VERSION 5.8 ;
BUSBITCHARS "[]" ;
DIVIDERCHAR "/" ;
UNITS
    DATABASE MICRONS 1000 ;
END UNITS

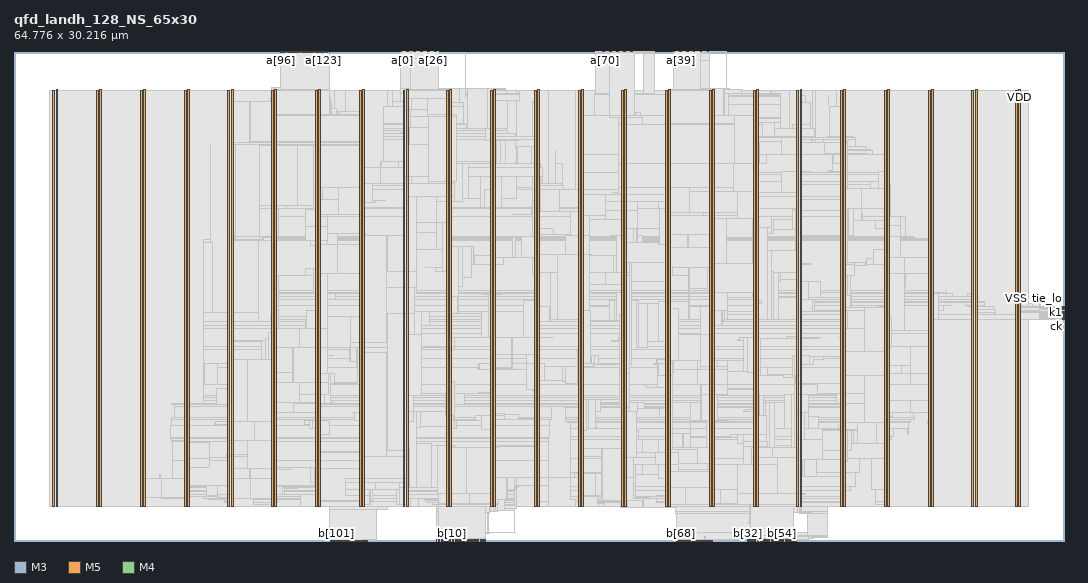
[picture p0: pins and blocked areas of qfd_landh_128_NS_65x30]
MACRO qfd_landh_128_NS_65x30
  FOREIGN qfd_landh_128_NS_65x30 0 0 ;
  CLASS BLOCK ;
  SIZE 64.776 BY 30.216 ;
  PIN a[0]
    DIRECTION INPUT ;
    USE SIGNAL ;
    PORT
      LAYER M3 ;
        RECT  23.94 30.179 23.958 30.216 ;
    END
  END a[0]
  PIN a[100]
    DIRECTION INPUT ;
    USE SIGNAL ;
    PORT
      LAYER M5 ;
        RECT  16.848 30.132 16.872 30.216 ;
    END
  END a[100]
  PIN a[101]
    DIRECTION INPUT ;
    USE SIGNAL ;
    PORT
      LAYER M5 ;
        RECT  16.944 30.132 16.968 30.216 ;
    END
  END a[101]
  PIN a[102]
    DIRECTION INPUT ;
    USE SIGNAL ;
    PORT
      LAYER M5 ;
        RECT  17.04 30.132 17.064 30.216 ;
    END
  END a[102]
  PIN a[103]
    DIRECTION INPUT ;
    USE SIGNAL ;
    PORT
      LAYER M5 ;
        RECT  17.136 30.132 17.16 30.216 ;
    END
  END a[103]
  PIN a[104]
    DIRECTION INPUT ;
    USE SIGNAL ;
    PORT
      LAYER M5 ;
        RECT  17.232 30.132 17.256 30.216 ;
    END
  END a[104]
  PIN a[105]
    DIRECTION INPUT ;
    USE SIGNAL ;
    PORT
      LAYER M5 ;
        RECT  17.328 30.132 17.352 30.216 ;
    END
  END a[105]
  PIN a[106]
    DIRECTION INPUT ;
    USE SIGNAL ;
    PORT
      LAYER M5 ;
        RECT  17.424 30.132 17.448 30.216 ;
    END
  END a[106]
  PIN a[107]
    DIRECTION INPUT ;
    USE SIGNAL ;
    PORT
      LAYER M5 ;
        RECT  17.52 30.132 17.544 30.216 ;
    END
  END a[107]
  PIN a[108]
    DIRECTION INPUT ;
    USE SIGNAL ;
    PORT
      LAYER M5 ;
        RECT  17.616 30.132 17.64 30.216 ;
    END
  END a[108]
  PIN a[109]
    DIRECTION INPUT ;
    USE SIGNAL ;
    PORT
      LAYER M5 ;
        RECT  17.712 30.132 17.736 30.216 ;
    END
  END a[109]
  PIN a[10]
    DIRECTION INPUT ;
    USE SIGNAL ;
    PORT
      LAYER M3 ;
        RECT  24.66 30.179 24.678 30.216 ;
    END
  END a[10]
  PIN a[110]
    DIRECTION INPUT ;
    USE SIGNAL ;
    PORT
      LAYER M5 ;
        RECT  17.808 30.132 17.832 30.216 ;
    END
  END a[110]
  PIN a[111]
    DIRECTION INPUT ;
    USE SIGNAL ;
    PORT
      LAYER M5 ;
        RECT  17.904 30.132 17.928 30.216 ;
    END
  END a[111]
  PIN a[112]
    DIRECTION INPUT ;
    USE SIGNAL ;
    PORT
      LAYER M5 ;
        RECT  18 30.132 18.024 30.216 ;
    END
  END a[112]
  PIN a[113]
    DIRECTION INPUT ;
    USE SIGNAL ;
    PORT
      LAYER M5 ;
        RECT  18.096 30.132 18.12 30.216 ;
    END
  END a[113]
  PIN a[114]
    DIRECTION INPUT ;
    USE SIGNAL ;
    PORT
      LAYER M5 ;
        RECT  18.192 30.132 18.216 30.216 ;
    END
  END a[114]
  PIN a[115]
    DIRECTION INPUT ;
    USE SIGNAL ;
    PORT
      LAYER M5 ;
        RECT  18.288 30.132 18.312 30.216 ;
    END
  END a[115]
  PIN a[116]
    DIRECTION INPUT ;
    USE SIGNAL ;
    PORT
      LAYER M5 ;
        RECT  18.384 30.132 18.408 30.216 ;
    END
  END a[116]
  PIN a[117]
    DIRECTION INPUT ;
    USE SIGNAL ;
    PORT
      LAYER M5 ;
        RECT  18.48 30.132 18.504 30.216 ;
    END
  END a[117]
  PIN a[118]
    DIRECTION INPUT ;
    USE SIGNAL ;
    PORT
      LAYER M5 ;
        RECT  18.576 30.132 18.6 30.216 ;
    END
  END a[118]
  PIN a[119]
    DIRECTION INPUT ;
    USE SIGNAL ;
    PORT
      LAYER M5 ;
        RECT  18.672 30.132 18.696 30.216 ;
    END
  END a[119]
  PIN a[11]
    DIRECTION INPUT ;
    USE SIGNAL ;
    PORT
      LAYER M3 ;
        RECT  24.732 30.179 24.75 30.216 ;
    END
  END a[11]
  PIN a[120]
    DIRECTION INPUT ;
    USE SIGNAL ;
    PORT
      LAYER M5 ;
        RECT  18.768 30.132 18.792 30.216 ;
    END
  END a[120]
  PIN a[121]
    DIRECTION INPUT ;
    USE SIGNAL ;
    PORT
      LAYER M5 ;
        RECT  18.864 30.132 18.888 30.216 ;
    END
  END a[121]
  PIN a[122]
    DIRECTION INPUT ;
    USE SIGNAL ;
    PORT
      LAYER M5 ;
        RECT  18.96 30.132 18.984 30.216 ;
    END
  END a[122]
  PIN a[123]
    DIRECTION INPUT ;
    USE SIGNAL ;
    PORT
      LAYER M5 ;
        RECT  19.056 30.132 19.08 30.216 ;
    END
  END a[123]
  PIN a[124]
    DIRECTION INPUT ;
    USE SIGNAL ;
    PORT
      LAYER M5 ;
        RECT  19.152 30.132 19.176 30.216 ;
    END
  END a[124]
  PIN a[125]
    DIRECTION INPUT ;
    USE SIGNAL ;
    PORT
      LAYER M5 ;
        RECT  19.248 30.132 19.272 30.216 ;
    END
  END a[125]
  PIN a[126]
    DIRECTION INPUT ;
    USE SIGNAL ;
    PORT
      LAYER M5 ;
        RECT  19.344 30.132 19.368 30.216 ;
    END
  END a[126]
  PIN a[127]
    DIRECTION INPUT ;
    USE SIGNAL ;
    PORT
      LAYER M5 ;
        RECT  19.44 30.132 19.464 30.216 ;
    END
  END a[127]
  PIN a[12]
    DIRECTION INPUT ;
    USE SIGNAL ;
    PORT
      LAYER M3 ;
        RECT  24.804 30.179 24.822 30.216 ;
    END
  END a[12]
  PIN a[13]
    DIRECTION INPUT ;
    USE SIGNAL ;
    PORT
      LAYER M3 ;
        RECT  24.876 30.179 24.894 30.216 ;
    END
  END a[13]
  PIN a[14]
    DIRECTION INPUT ;
    USE SIGNAL ;
    PORT
      LAYER M3 ;
        RECT  24.948 30.179 24.966 30.216 ;
    END
  END a[14]
  PIN a[15]
    DIRECTION INPUT ;
    USE SIGNAL ;
    PORT
      LAYER M3 ;
        RECT  25.02 30.179 25.038 30.216 ;
    END
  END a[15]
  PIN a[16]
    DIRECTION INPUT ;
    USE SIGNAL ;
    PORT
      LAYER M3 ;
        RECT  25.092 30.179 25.11 30.216 ;
    END
  END a[16]
  PIN a[17]
    DIRECTION INPUT ;
    USE SIGNAL ;
    PORT
      LAYER M3 ;
        RECT  25.164 30.179 25.182 30.216 ;
    END
  END a[17]
  PIN a[18]
    DIRECTION INPUT ;
    USE SIGNAL ;
    PORT
      LAYER M3 ;
        RECT  25.236 30.179 25.254 30.216 ;
    END
  END a[18]
  PIN a[19]
    DIRECTION INPUT ;
    USE SIGNAL ;
    PORT
      LAYER M3 ;
        RECT  25.308 30.179 25.326 30.216 ;
    END
  END a[19]
  PIN a[1]
    DIRECTION INPUT ;
    USE SIGNAL ;
    PORT
      LAYER M3 ;
        RECT  24.012 30.179 24.03 30.216 ;
    END
  END a[1]
  PIN a[20]
    DIRECTION INPUT ;
    USE SIGNAL ;
    PORT
      LAYER M3 ;
        RECT  25.38 30.179 25.398 30.216 ;
    END
  END a[20]
  PIN a[21]
    DIRECTION INPUT ;
    USE SIGNAL ;
    PORT
      LAYER M3 ;
        RECT  25.452 30.179 25.47 30.216 ;
    END
  END a[21]
  PIN a[22]
    DIRECTION INPUT ;
    USE SIGNAL ;
    PORT
      LAYER M3 ;
        RECT  25.524 30.179 25.542 30.216 ;
    END
  END a[22]
  PIN a[23]
    DIRECTION INPUT ;
    USE SIGNAL ;
    PORT
      LAYER M3 ;
        RECT  25.596 30.179 25.614 30.216 ;
    END
  END a[23]
  PIN a[24]
    DIRECTION INPUT ;
    USE SIGNAL ;
    PORT
      LAYER M3 ;
        RECT  25.668 30.179 25.686 30.216 ;
    END
  END a[24]
  PIN a[25]
    DIRECTION INPUT ;
    USE SIGNAL ;
    PORT
      LAYER M3 ;
        RECT  25.74 30.179 25.758 30.216 ;
    END
  END a[25]
  PIN a[26]
    DIRECTION INPUT ;
    USE SIGNAL ;
    PORT
      LAYER M3 ;
        RECT  25.812 30.179 25.83 30.216 ;
    END
  END a[26]
  PIN a[27]
    DIRECTION INPUT ;
    USE SIGNAL ;
    PORT
      LAYER M3 ;
        RECT  25.884 30.179 25.902 30.216 ;
    END
  END a[27]
  PIN a[28]
    DIRECTION INPUT ;
    USE SIGNAL ;
    PORT
      LAYER M3 ;
        RECT  25.956 30.179 25.974 30.216 ;
    END
  END a[28]
  PIN a[29]
    DIRECTION INPUT ;
    USE SIGNAL ;
    PORT
      LAYER M3 ;
        RECT  26.028 30.179 26.046 30.216 ;
    END
  END a[29]
  PIN a[2]
    DIRECTION INPUT ;
    USE SIGNAL ;
    PORT
      LAYER M3 ;
        RECT  24.084 30.179 24.102 30.216 ;
    END
  END a[2]
  PIN a[30]
    DIRECTION INPUT ;
    USE SIGNAL ;
    PORT
      LAYER M3 ;
        RECT  26.1 30.179 26.118 30.216 ;
    END
  END a[30]
  PIN a[31]
    DIRECTION INPUT ;
    USE SIGNAL ;
    PORT
      LAYER M3 ;
        RECT  26.172 30.179 26.19 30.216 ;
    END
  END a[31]
  PIN a[32]
    DIRECTION INPUT ;
    USE SIGNAL ;
    PORT
      LAYER M3 ;
        RECT  40.644 30.179 40.662 30.216 ;
    END
  END a[32]
  PIN a[33]
    DIRECTION INPUT ;
    USE SIGNAL ;
    PORT
      LAYER M3 ;
        RECT  40.716 30.179 40.734 30.216 ;
    END
  END a[33]
  PIN a[34]
    DIRECTION INPUT ;
    USE SIGNAL ;
    PORT
      LAYER M3 ;
        RECT  40.788 30.179 40.806 30.216 ;
    END
  END a[34]
  PIN a[35]
    DIRECTION INPUT ;
    USE SIGNAL ;
    PORT
      LAYER M3 ;
        RECT  40.86 30.179 40.878 30.216 ;
    END
  END a[35]
  PIN a[36]
    DIRECTION INPUT ;
    USE SIGNAL ;
    PORT
      LAYER M3 ;
        RECT  40.932 30.179 40.95 30.216 ;
    END
  END a[36]
  PIN a[37]
    DIRECTION INPUT ;
    USE SIGNAL ;
    PORT
      LAYER M3 ;
        RECT  41.004 30.179 41.022 30.216 ;
    END
  END a[37]
  PIN a[38]
    DIRECTION INPUT ;
    USE SIGNAL ;
    PORT
      LAYER M3 ;
        RECT  41.076 30.179 41.094 30.216 ;
    END
  END a[38]
  PIN a[39]
    DIRECTION INPUT ;
    USE SIGNAL ;
    PORT
      LAYER M3 ;
        RECT  41.148 30.179 41.166 30.216 ;
    END
  END a[39]
  PIN a[3]
    DIRECTION INPUT ;
    USE SIGNAL ;
    PORT
      LAYER M3 ;
        RECT  24.156 30.179 24.174 30.216 ;
    END
  END a[3]
  PIN a[40]
    DIRECTION INPUT ;
    USE SIGNAL ;
    PORT
      LAYER M3 ;
        RECT  41.22 30.179 41.238 30.216 ;
    END
  END a[40]
  PIN a[41]
    DIRECTION INPUT ;
    USE SIGNAL ;
    PORT
      LAYER M3 ;
        RECT  41.292 30.179 41.31 30.216 ;
    END
  END a[41]
  PIN a[42]
    DIRECTION INPUT ;
    USE SIGNAL ;
    PORT
      LAYER M3 ;
        RECT  41.364 30.179 41.382 30.216 ;
    END
  END a[42]
  PIN a[43]
    DIRECTION INPUT ;
    USE SIGNAL ;
    PORT
      LAYER M3 ;
        RECT  41.436 30.179 41.454 30.216 ;
    END
  END a[43]
  PIN a[44]
    DIRECTION INPUT ;
    USE SIGNAL ;
    PORT
      LAYER M3 ;
        RECT  41.508 30.179 41.526 30.216 ;
    END
  END a[44]
  PIN a[45]
    DIRECTION INPUT ;
    USE SIGNAL ;
    PORT
      LAYER M3 ;
        RECT  41.58 30.179 41.598 30.216 ;
    END
  END a[45]
  PIN a[46]
    DIRECTION INPUT ;
    USE SIGNAL ;
    PORT
      LAYER M3 ;
        RECT  41.652 30.179 41.67 30.216 ;
    END
  END a[46]
  PIN a[47]
    DIRECTION INPUT ;
    USE SIGNAL ;
    PORT
      LAYER M3 ;
        RECT  41.724 30.179 41.742 30.216 ;
    END
  END a[47]
  PIN a[48]
    DIRECTION INPUT ;
    USE SIGNAL ;
    PORT
      LAYER M3 ;
        RECT  41.796 30.179 41.814 30.216 ;
    END
  END a[48]
  PIN a[49]
    DIRECTION INPUT ;
    USE SIGNAL ;
    PORT
      LAYER M3 ;
        RECT  41.868 30.179 41.886 30.216 ;
    END
  END a[49]
  PIN a[4]
    DIRECTION INPUT ;
    USE SIGNAL ;
    PORT
      LAYER M3 ;
        RECT  24.228 30.179 24.246 30.216 ;
    END
  END a[4]
  PIN a[50]
    DIRECTION INPUT ;
    USE SIGNAL ;
    PORT
      LAYER M3 ;
        RECT  41.94 30.179 41.958 30.216 ;
    END
  END a[50]
  PIN a[51]
    DIRECTION INPUT ;
    USE SIGNAL ;
    PORT
      LAYER M3 ;
        RECT  42.012 30.179 42.03 30.216 ;
    END
  END a[51]
  PIN a[52]
    DIRECTION INPUT ;
    USE SIGNAL ;
    PORT
      LAYER M3 ;
        RECT  42.084 30.179 42.102 30.216 ;
    END
  END a[52]
  PIN a[53]
    DIRECTION INPUT ;
    USE SIGNAL ;
    PORT
      LAYER M3 ;
        RECT  42.156 30.179 42.174 30.216 ;
    END
  END a[53]
  PIN a[54]
    DIRECTION INPUT ;
    USE SIGNAL ;
    PORT
      LAYER M3 ;
        RECT  42.228 30.179 42.246 30.216 ;
    END
  END a[54]
  PIN a[55]
    DIRECTION INPUT ;
    USE SIGNAL ;
    PORT
      LAYER M3 ;
        RECT  42.3 30.179 42.318 30.216 ;
    END
  END a[55]
  PIN a[56]
    DIRECTION INPUT ;
    USE SIGNAL ;
    PORT
      LAYER M3 ;
        RECT  42.372 30.179 42.39 30.216 ;
    END
  END a[56]
  PIN a[57]
    DIRECTION INPUT ;
    USE SIGNAL ;
    PORT
      LAYER M3 ;
        RECT  42.444 30.179 42.462 30.216 ;
    END
  END a[57]
  PIN a[58]
    DIRECTION INPUT ;
    USE SIGNAL ;
    PORT
      LAYER M3 ;
        RECT  42.516 30.179 42.534 30.216 ;
    END
  END a[58]
  PIN a[59]
    DIRECTION INPUT ;
    USE SIGNAL ;
    PORT
      LAYER M3 ;
        RECT  42.588 30.179 42.606 30.216 ;
    END
  END a[59]
  PIN a[5]
    DIRECTION INPUT ;
    USE SIGNAL ;
    PORT
      LAYER M3 ;
        RECT  24.3 30.179 24.318 30.216 ;
    END
  END a[5]
  PIN a[60]
    DIRECTION INPUT ;
    USE SIGNAL ;
    PORT
      LAYER M3 ;
        RECT  42.66 30.179 42.678 30.216 ;
    END
  END a[60]
  PIN a[61]
    DIRECTION INPUT ;
    USE SIGNAL ;
    PORT
      LAYER M3 ;
        RECT  42.732 30.179 42.75 30.216 ;
    END
  END a[61]
  PIN a[62]
    DIRECTION INPUT ;
    USE SIGNAL ;
    PORT
      LAYER M3 ;
        RECT  42.804 30.179 42.822 30.216 ;
    END
  END a[62]
  PIN a[63]
    DIRECTION INPUT ;
    USE SIGNAL ;
    PORT
      LAYER M3 ;
        RECT  42.876 30.179 42.894 30.216 ;
    END
  END a[63]
  PIN a[64]
    DIRECTION INPUT ;
    USE SIGNAL ;
    PORT
      LAYER M3 ;
        RECT  36.036 30.179 36.054 30.216 ;
    END
  END a[64]
  PIN a[65]
    DIRECTION INPUT ;
    USE SIGNAL ;
    PORT
      LAYER M3 ;
        RECT  36.108 30.179 36.126 30.216 ;
    END
  END a[65]
  PIN a[66]
    DIRECTION INPUT ;
    USE SIGNAL ;
    PORT
      LAYER M3 ;
        RECT  36.18 30.179 36.198 30.216 ;
    END
  END a[66]
  PIN a[67]
    DIRECTION INPUT ;
    USE SIGNAL ;
    PORT
      LAYER M3 ;
        RECT  36.252 30.179 36.27 30.216 ;
    END
  END a[67]
  PIN a[68]
    DIRECTION INPUT ;
    USE SIGNAL ;
    PORT
      LAYER M3 ;
        RECT  36.324 30.179 36.342 30.216 ;
    END
  END a[68]
  PIN a[69]
    DIRECTION INPUT ;
    USE SIGNAL ;
    PORT
      LAYER M3 ;
        RECT  36.396 30.179 36.414 30.216 ;
    END
  END a[69]
  PIN a[6]
    DIRECTION INPUT ;
    USE SIGNAL ;
    PORT
      LAYER M3 ;
        RECT  24.372 30.179 24.39 30.216 ;
    END
  END a[6]
  PIN a[70]
    DIRECTION INPUT ;
    USE SIGNAL ;
    PORT
      LAYER M3 ;
        RECT  36.468 30.179 36.486 30.216 ;
    END
  END a[70]
  PIN a[71]
    DIRECTION INPUT ;
    USE SIGNAL ;
    PORT
      LAYER M3 ;
        RECT  36.54 30.179 36.558 30.216 ;
    END
  END a[71]
  PIN a[72]
    DIRECTION INPUT ;
    USE SIGNAL ;
    PORT
      LAYER M3 ;
        RECT  36.612 30.179 36.63 30.216 ;
    END
  END a[72]
  PIN a[73]
    DIRECTION INPUT ;
    USE SIGNAL ;
    PORT
      LAYER M3 ;
        RECT  36.684 30.179 36.702 30.216 ;
    END
  END a[73]
  PIN a[74]
    DIRECTION INPUT ;
    USE SIGNAL ;
    PORT
      LAYER M3 ;
        RECT  36.756 30.179 36.774 30.216 ;
    END
  END a[74]
  PIN a[75]
    DIRECTION INPUT ;
    USE SIGNAL ;
    PORT
      LAYER M3 ;
        RECT  36.828 30.179 36.846 30.216 ;
    END
  END a[75]
  PIN a[76]
    DIRECTION INPUT ;
    USE SIGNAL ;
    PORT
      LAYER M3 ;
        RECT  36.9 30.179 36.918 30.216 ;
    END
  END a[76]
  PIN a[77]
    DIRECTION INPUT ;
    USE SIGNAL ;
    PORT
      LAYER M3 ;
        RECT  36.972 30.179 36.99 30.216 ;
    END
  END a[77]
  PIN a[78]
    DIRECTION INPUT ;
    USE SIGNAL ;
    PORT
      LAYER M3 ;
        RECT  37.044 30.179 37.062 30.216 ;
    END
  END a[78]
  PIN a[79]
    DIRECTION INPUT ;
    USE SIGNAL ;
    PORT
      LAYER M3 ;
        RECT  37.116 30.179 37.134 30.216 ;
    END
  END a[79]
  PIN a[7]
    DIRECTION INPUT ;
    USE SIGNAL ;
    PORT
      LAYER M3 ;
        RECT  24.444 30.179 24.462 30.216 ;
    END
  END a[7]
  PIN a[80]
    DIRECTION INPUT ;
    USE SIGNAL ;
    PORT
      LAYER M3 ;
        RECT  37.188 30.179 37.206 30.216 ;
    END
  END a[80]
  PIN a[81]
    DIRECTION INPUT ;
    USE SIGNAL ;
    PORT
      LAYER M3 ;
        RECT  37.26 30.179 37.278 30.216 ;
    END
  END a[81]
  PIN a[82]
    DIRECTION INPUT ;
    USE SIGNAL ;
    PORT
      LAYER M3 ;
        RECT  37.332 30.179 37.35 30.216 ;
    END
  END a[82]
  PIN a[83]
    DIRECTION INPUT ;
    USE SIGNAL ;
    PORT
      LAYER M3 ;
        RECT  37.404 30.179 37.422 30.216 ;
    END
  END a[83]
  PIN a[84]
    DIRECTION INPUT ;
    USE SIGNAL ;
    PORT
      LAYER M3 ;
        RECT  37.476 30.179 37.494 30.216 ;
    END
  END a[84]
  PIN a[85]
    DIRECTION INPUT ;
    USE SIGNAL ;
    PORT
      LAYER M3 ;
        RECT  37.548 30.179 37.566 30.216 ;
    END
  END a[85]
  PIN a[86]
    DIRECTION INPUT ;
    USE SIGNAL ;
    PORT
      LAYER M3 ;
        RECT  37.62 30.179 37.638 30.216 ;
    END
  END a[86]
  PIN a[87]
    DIRECTION INPUT ;
    USE SIGNAL ;
    PORT
      LAYER M3 ;
        RECT  37.692 30.179 37.71 30.216 ;
    END
  END a[87]
  PIN a[88]
    DIRECTION INPUT ;
    USE SIGNAL ;
    PORT
      LAYER M3 ;
        RECT  37.764 30.179 37.782 30.216 ;
    END
  END a[88]
  PIN a[89]
    DIRECTION INPUT ;
    USE SIGNAL ;
    PORT
      LAYER M3 ;
        RECT  37.836 30.179 37.854 30.216 ;
    END
  END a[89]
  PIN a[8]
    DIRECTION INPUT ;
    USE SIGNAL ;
    PORT
      LAYER M3 ;
        RECT  24.516 30.179 24.534 30.216 ;
    END
  END a[8]
  PIN a[90]
    DIRECTION INPUT ;
    USE SIGNAL ;
    PORT
      LAYER M3 ;
        RECT  37.908 30.179 37.926 30.216 ;
    END
  END a[90]
  PIN a[91]
    DIRECTION INPUT ;
    USE SIGNAL ;
    PORT
      LAYER M3 ;
        RECT  37.98 30.179 37.998 30.216 ;
    END
  END a[91]
  PIN a[92]
    DIRECTION INPUT ;
    USE SIGNAL ;
    PORT
      LAYER M3 ;
        RECT  38.052 30.179 38.07 30.216 ;
    END
  END a[92]
  PIN a[93]
    DIRECTION INPUT ;
    USE SIGNAL ;
    PORT
      LAYER M3 ;
        RECT  38.124 30.179 38.142 30.216 ;
    END
  END a[93]
  PIN a[94]
    DIRECTION INPUT ;
    USE SIGNAL ;
    PORT
      LAYER M3 ;
        RECT  38.196 30.179 38.214 30.216 ;
    END
  END a[94]
  PIN a[95]
    DIRECTION INPUT ;
    USE SIGNAL ;
    PORT
      LAYER M3 ;
        RECT  38.268 30.179 38.286 30.216 ;
    END
  END a[95]
  PIN a[96]
    DIRECTION INPUT ;
    USE SIGNAL ;
    PORT
      LAYER M5 ;
        RECT  16.464 30.132 16.488 30.216 ;
    END
  END a[96]
  PIN a[97]
    DIRECTION INPUT ;
    USE SIGNAL ;
    PORT
      LAYER M5 ;
        RECT  16.56 30.132 16.584 30.216 ;
    END
  END a[97]
  PIN a[98]
    DIRECTION INPUT ;
    USE SIGNAL ;
    PORT
      LAYER M5 ;
        RECT  16.656 30.132 16.68 30.216 ;
    END
  END a[98]
  PIN a[99]
    DIRECTION INPUT ;
    USE SIGNAL ;
    PORT
      LAYER M5 ;
        RECT  16.752 30.132 16.776 30.216 ;
    END
  END a[99]
  PIN a[9]
    DIRECTION INPUT ;
    USE SIGNAL ;
    PORT
      LAYER M3 ;
        RECT  24.588 30.179 24.606 30.216 ;
    END
  END a[9]
  PIN b[0]
    DIRECTION OUTPUT ;
    USE SIGNAL ;
    PORT
      LAYER M5 ;
        RECT  26.064 0 26.088 0.084 ;
    END
  END b[0]
  PIN b[100]
    DIRECTION OUTPUT ;
    USE SIGNAL ;
    PORT
      LAYER M3 ;
        RECT  19.836 0 19.854 0.037 ;
    END
  END b[100]
  PIN b[101]
    DIRECTION OUTPUT ;
    USE SIGNAL ;
    PORT
      LAYER M3 ;
        RECT  19.908 0 19.926 0.037 ;
    END
  END b[101]
  PIN b[102]
    DIRECTION OUTPUT ;
    USE SIGNAL ;
    PORT
      LAYER M3 ;
        RECT  19.98 0 19.998 0.037 ;
    END
  END b[102]
  PIN b[103]
    DIRECTION OUTPUT ;
    USE SIGNAL ;
    PORT
      LAYER M3 ;
        RECT  20.052 0 20.07 0.037 ;
    END
  END b[103]
  PIN b[104]
    DIRECTION OUTPUT ;
    USE SIGNAL ;
    PORT
      LAYER M3 ;
        RECT  20.124 0 20.142 0.037 ;
    END
  END b[104]
  PIN b[105]
    DIRECTION OUTPUT ;
    USE SIGNAL ;
    PORT
      LAYER M3 ;
        RECT  20.196 0 20.214 0.037 ;
    END
  END b[105]
  PIN b[106]
    DIRECTION OUTPUT ;
    USE SIGNAL ;
    PORT
      LAYER M3 ;
        RECT  20.268 0 20.286 0.037 ;
    END
  END b[106]
  PIN b[107]
    DIRECTION OUTPUT ;
    USE SIGNAL ;
    PORT
      LAYER M3 ;
        RECT  20.34 0 20.358 0.037 ;
    END
  END b[107]
  PIN b[108]
    DIRECTION OUTPUT ;
    USE SIGNAL ;
    PORT
      LAYER M3 ;
        RECT  20.412 0 20.43 0.037 ;
    END
  END b[108]
  PIN b[109]
    DIRECTION OUTPUT ;
    USE SIGNAL ;
    PORT
      LAYER M3 ;
        RECT  20.484 0 20.502 0.037 ;
    END
  END b[109]
  PIN b[10]
    DIRECTION OUTPUT ;
    USE SIGNAL ;
    PORT
      LAYER M5 ;
        RECT  27.024 0 27.048 0.084 ;
    END
  END b[10]
  PIN b[110]
    DIRECTION OUTPUT ;
    USE SIGNAL ;
    PORT
      LAYER M3 ;
        RECT  20.556 0 20.574 0.037 ;
    END
  END b[110]
  PIN b[111]
    DIRECTION OUTPUT ;
    USE SIGNAL ;
    PORT
      LAYER M3 ;
        RECT  20.628 0 20.646 0.037 ;
    END
  END b[111]
  PIN b[112]
    DIRECTION OUTPUT ;
    USE SIGNAL ;
    PORT
      LAYER M3 ;
        RECT  20.7 0 20.718 0.037 ;
    END
  END b[112]
  PIN b[113]
    DIRECTION OUTPUT ;
    USE SIGNAL ;
    PORT
      LAYER M3 ;
        RECT  20.772 0 20.79 0.037 ;
    END
  END b[113]
  PIN b[114]
    DIRECTION OUTPUT ;
    USE SIGNAL ;
    PORT
      LAYER M3 ;
        RECT  20.844 0 20.862 0.037 ;
    END
  END b[114]
  PIN b[115]
    DIRECTION OUTPUT ;
    USE SIGNAL ;
    PORT
      LAYER M3 ;
        RECT  20.916 0 20.934 0.037 ;
    END
  END b[115]
  PIN b[116]
    DIRECTION OUTPUT ;
    USE SIGNAL ;
    PORT
      LAYER M3 ;
        RECT  20.988 0 21.006 0.037 ;
    END
  END b[116]
  PIN b[117]
    DIRECTION OUTPUT ;
    USE SIGNAL ;
    PORT
      LAYER M3 ;
        RECT  21.06 0 21.078 0.037 ;
    END
  END b[117]
  PIN b[118]
    DIRECTION OUTPUT ;
    USE SIGNAL ;
    PORT
      LAYER M3 ;
        RECT  21.132 0 21.15 0.037 ;
    END
  END b[118]
  PIN b[119]
    DIRECTION OUTPUT ;
    USE SIGNAL ;
    PORT
      LAYER M3 ;
        RECT  21.204 0 21.222 0.037 ;
    END
  END b[119]
  PIN b[11]
    DIRECTION OUTPUT ;
    USE SIGNAL ;
    PORT
      LAYER M5 ;
        RECT  27.12 0 27.144 0.084 ;
    END
  END b[11]
  PIN b[120]
    DIRECTION OUTPUT ;
    USE SIGNAL ;
    PORT
      LAYER M3 ;
        RECT  21.276 0 21.294 0.037 ;
    END
  END b[120]
  PIN b[121]
    DIRECTION OUTPUT ;
    USE SIGNAL ;
    PORT
      LAYER M3 ;
        RECT  21.348 0 21.366 0.037 ;
    END
  END b[121]
  PIN b[122]
    DIRECTION OUTPUT ;
    USE SIGNAL ;
    PORT
      LAYER M3 ;
        RECT  21.42 0 21.438 0.037 ;
    END
  END b[122]
  PIN b[123]
    DIRECTION OUTPUT ;
    USE SIGNAL ;
    PORT
      LAYER M3 ;
        RECT  21.492 0 21.51 0.037 ;
    END
  END b[123]
  PIN b[124]
    DIRECTION OUTPUT ;
    USE SIGNAL ;
    PORT
      LAYER M3 ;
        RECT  21.564 0 21.582 0.037 ;
    END
  END b[124]
  PIN b[125]
    DIRECTION OUTPUT ;
    USE SIGNAL ;
    PORT
      LAYER M3 ;
        RECT  21.636 0 21.654 0.037 ;
    END
  END b[125]
  PIN b[126]
    DIRECTION OUTPUT ;
    USE SIGNAL ;
    PORT
      LAYER M3 ;
        RECT  21.708 0 21.726 0.037 ;
    END
  END b[126]
  PIN b[127]
    DIRECTION OUTPUT ;
    USE SIGNAL ;
    PORT
      LAYER M3 ;
        RECT  21.78 0 21.798 0.037 ;
    END
  END b[127]
  PIN b[12]
    DIRECTION OUTPUT ;
    USE SIGNAL ;
    PORT
      LAYER M5 ;
        RECT  27.216 0 27.24 0.084 ;
    END
  END b[12]
  PIN b[13]
    DIRECTION OUTPUT ;
    USE SIGNAL ;
    PORT
      LAYER M5 ;
        RECT  27.312 0 27.336 0.084 ;
    END
  END b[13]
  PIN b[14]
    DIRECTION OUTPUT ;
    USE SIGNAL ;
    PORT
      LAYER M5 ;
        RECT  27.408 0 27.432 0.084 ;
    END
  END b[14]
  PIN b[15]
    DIRECTION OUTPUT ;
    USE SIGNAL ;
    PORT
      LAYER M5 ;
        RECT  27.504 0 27.528 0.084 ;
    END
  END b[15]
  PIN b[16]
    DIRECTION OUTPUT ;
    USE SIGNAL ;
    PORT
      LAYER M5 ;
        RECT  27.6 0 27.624 0.084 ;
    END
  END b[16]
  PIN b[17]
    DIRECTION OUTPUT ;
    USE SIGNAL ;
    PORT
      LAYER M5 ;
        RECT  27.696 0 27.72 0.084 ;
    END
  END b[17]
  PIN b[18]
    DIRECTION OUTPUT ;
    USE SIGNAL ;
    PORT
      LAYER M5 ;
        RECT  27.792 0 27.816 0.084 ;
    END
  END b[18]
  PIN b[19]
    DIRECTION OUTPUT ;
    USE SIGNAL ;
    PORT
      LAYER M5 ;
        RECT  27.888 0 27.912 0.084 ;
    END
  END b[19]
  PIN b[1]
    DIRECTION OUTPUT ;
    USE SIGNAL ;
    PORT
      LAYER M5 ;
        RECT  26.16 0 26.184 0.084 ;
    END
  END b[1]
  PIN b[20]
    DIRECTION OUTPUT ;
    USE SIGNAL ;
    PORT
      LAYER M5 ;
        RECT  27.984 0 28.008 0.084 ;
    END
  END b[20]
  PIN b[21]
    DIRECTION OUTPUT ;
    USE SIGNAL ;
    PORT
      LAYER M5 ;
        RECT  28.08 0 28.104 0.084 ;
    END
  END b[21]
  PIN b[22]
    DIRECTION OUTPUT ;
    USE SIGNAL ;
    PORT
      LAYER M5 ;
        RECT  28.176 0 28.2 0.084 ;
    END
  END b[22]
  PIN b[23]
    DIRECTION OUTPUT ;
    USE SIGNAL ;
    PORT
      LAYER M5 ;
        RECT  28.272 0 28.296 0.084 ;
    END
  END b[23]
  PIN b[24]
    DIRECTION OUTPUT ;
    USE SIGNAL ;
    PORT
      LAYER M5 ;
        RECT  28.368 0 28.392 0.084 ;
    END
  END b[24]
  PIN b[25]
    DIRECTION OUTPUT ;
    USE SIGNAL ;
    PORT
      LAYER M5 ;
        RECT  28.464 0 28.488 0.084 ;
    END
  END b[25]
  PIN b[26]
    DIRECTION OUTPUT ;
    USE SIGNAL ;
    PORT
      LAYER M5 ;
        RECT  28.56 0 28.584 0.084 ;
    END
  END b[26]
  PIN b[27]
    DIRECTION OUTPUT ;
    USE SIGNAL ;
    PORT
      LAYER M5 ;
        RECT  28.656 0 28.68 0.084 ;
    END
  END b[27]
  PIN b[28]
    DIRECTION OUTPUT ;
    USE SIGNAL ;
    PORT
      LAYER M5 ;
        RECT  28.752 0 28.776 0.084 ;
    END
  END b[28]
  PIN b[29]
    DIRECTION OUTPUT ;
    USE SIGNAL ;
    PORT
      LAYER M5 ;
        RECT  28.848 0 28.872 0.084 ;
    END
  END b[29]
  PIN b[2]
    DIRECTION OUTPUT ;
    USE SIGNAL ;
    PORT
      LAYER M5 ;
        RECT  26.256 0 26.28 0.084 ;
    END
  END b[2]
  PIN b[30]
    DIRECTION OUTPUT ;
    USE SIGNAL ;
    PORT
      LAYER M5 ;
        RECT  28.944 0 28.968 0.084 ;
    END
  END b[30]
  PIN b[31]
    DIRECTION OUTPUT ;
    USE SIGNAL ;
    PORT
      LAYER M5 ;
        RECT  29.04 0 29.064 0.084 ;
    END
  END b[31]
  PIN b[32]
    DIRECTION OUTPUT ;
    USE SIGNAL ;
    PORT
      LAYER M5 ;
        RECT  45.264 0 45.288 0.084 ;
    END
  END b[32]
  PIN b[33]
    DIRECTION OUTPUT ;
    USE SIGNAL ;
    PORT
      LAYER M5 ;
        RECT  45.36 0 45.384 0.084 ;
    END
  END b[33]
  PIN b[34]
    DIRECTION OUTPUT ;
    USE SIGNAL ;
    PORT
      LAYER M5 ;
        RECT  45.456 0 45.48 0.084 ;
    END
  END b[34]
  PIN b[35]
    DIRECTION OUTPUT ;
    USE SIGNAL ;
    PORT
      LAYER M5 ;
        RECT  45.552 0 45.576 0.084 ;
    END
  END b[35]
  PIN b[36]
    DIRECTION OUTPUT ;
    USE SIGNAL ;
    PORT
      LAYER M5 ;
        RECT  45.648 0 45.672 0.084 ;
    END
  END b[36]
  PIN b[37]
    DIRECTION OUTPUT ;
    USE SIGNAL ;
    PORT
      LAYER M5 ;
        RECT  45.744 0 45.768 0.084 ;
    END
  END b[37]
  PIN b[38]
    DIRECTION OUTPUT ;
    USE SIGNAL ;
    PORT
      LAYER M5 ;
        RECT  45.84 0 45.864 0.084 ;
    END
  END b[38]
  PIN b[39]
    DIRECTION OUTPUT ;
    USE SIGNAL ;
    PORT
      LAYER M5 ;
        RECT  45.936 0 45.96 0.084 ;
    END
  END b[39]
  PIN b[3]
    DIRECTION OUTPUT ;
    USE SIGNAL ;
    PORT
      LAYER M5 ;
        RECT  26.352 0 26.376 0.084 ;
    END
  END b[3]
  PIN b[40]
    DIRECTION OUTPUT ;
    USE SIGNAL ;
    PORT
      LAYER M5 ;
        RECT  46.032 0 46.056 0.084 ;
    END
  END b[40]
  PIN b[41]
    DIRECTION OUTPUT ;
    USE SIGNAL ;
    PORT
      LAYER M5 ;
        RECT  46.128 0 46.152 0.084 ;
    END
  END b[41]
  PIN b[42]
    DIRECTION OUTPUT ;
    USE SIGNAL ;
    PORT
      LAYER M5 ;
        RECT  46.224 0 46.248 0.084 ;
    END
  END b[42]
  PIN b[43]
    DIRECTION OUTPUT ;
    USE SIGNAL ;
    PORT
      LAYER M5 ;
        RECT  46.32 0 46.344 0.084 ;
    END
  END b[43]
  PIN b[44]
    DIRECTION OUTPUT ;
    USE SIGNAL ;
    PORT
      LAYER M5 ;
        RECT  46.416 0 46.44 0.084 ;
    END
  END b[44]
  PIN b[45]
    DIRECTION OUTPUT ;
    USE SIGNAL ;
    PORT
      LAYER M5 ;
        RECT  46.512 0 46.536 0.084 ;
    END
  END b[45]
  PIN b[46]
    DIRECTION OUTPUT ;
    USE SIGNAL ;
    PORT
      LAYER M5 ;
        RECT  46.608 0 46.632 0.084 ;
    END
  END b[46]
  PIN b[47]
    DIRECTION OUTPUT ;
    USE SIGNAL ;
    PORT
      LAYER M5 ;
        RECT  46.704 0 46.728 0.084 ;
    END
  END b[47]
  PIN b[48]
    DIRECTION OUTPUT ;
    USE SIGNAL ;
    PORT
      LAYER M5 ;
        RECT  46.8 0 46.824 0.084 ;
    END
  END b[48]
  PIN b[49]
    DIRECTION OUTPUT ;
    USE SIGNAL ;
    PORT
      LAYER M5 ;
        RECT  46.896 0 46.92 0.084 ;
    END
  END b[49]
  PIN b[4]
    DIRECTION OUTPUT ;
    USE SIGNAL ;
    PORT
      LAYER M5 ;
        RECT  26.448 0 26.472 0.084 ;
    END
  END b[4]
  PIN b[50]
    DIRECTION OUTPUT ;
    USE SIGNAL ;
    PORT
      LAYER M5 ;
        RECT  46.992 0 47.016 0.084 ;
    END
  END b[50]
  PIN b[51]
    DIRECTION OUTPUT ;
    USE SIGNAL ;
    PORT
      LAYER M5 ;
        RECT  47.088 0 47.112 0.084 ;
    END
  END b[51]
  PIN b[52]
    DIRECTION OUTPUT ;
    USE SIGNAL ;
    PORT
      LAYER M5 ;
        RECT  47.184 0 47.208 0.084 ;
    END
  END b[52]
  PIN b[53]
    DIRECTION OUTPUT ;
    USE SIGNAL ;
    PORT
      LAYER M5 ;
        RECT  47.28 0 47.304 0.084 ;
    END
  END b[53]
  PIN b[54]
    DIRECTION OUTPUT ;
    USE SIGNAL ;
    PORT
      LAYER M5 ;
        RECT  47.376 0 47.4 0.084 ;
    END
  END b[54]
  PIN b[55]
    DIRECTION OUTPUT ;
    USE SIGNAL ;
    PORT
      LAYER M5 ;
        RECT  47.472 0 47.496 0.084 ;
    END
  END b[55]
  PIN b[56]
    DIRECTION OUTPUT ;
    USE SIGNAL ;
    PORT
      LAYER M5 ;
        RECT  47.568 0 47.592 0.084 ;
    END
  END b[56]
  PIN b[57]
    DIRECTION OUTPUT ;
    USE SIGNAL ;
    PORT
      LAYER M5 ;
        RECT  47.664 0 47.688 0.084 ;
    END
  END b[57]
  PIN b[58]
    DIRECTION OUTPUT ;
    USE SIGNAL ;
    PORT
      LAYER M5 ;
        RECT  47.76 0 47.784 0.084 ;
    END
  END b[58]
  PIN b[59]
    DIRECTION OUTPUT ;
    USE SIGNAL ;
    PORT
      LAYER M5 ;
        RECT  47.856 0 47.88 0.084 ;
    END
  END b[59]
  PIN b[5]
    DIRECTION OUTPUT ;
    USE SIGNAL ;
    PORT
      LAYER M5 ;
        RECT  26.544 0 26.568 0.084 ;
    END
  END b[5]
  PIN b[60]
    DIRECTION OUTPUT ;
    USE SIGNAL ;
    PORT
      LAYER M5 ;
        RECT  47.952 0 47.976 0.084 ;
    END
  END b[60]
  PIN b[61]
    DIRECTION OUTPUT ;
    USE SIGNAL ;
    PORT
      LAYER M5 ;
        RECT  48.048 0 48.072 0.084 ;
    END
  END b[61]
  PIN b[62]
    DIRECTION OUTPUT ;
    USE SIGNAL ;
    PORT
      LAYER M5 ;
        RECT  48.144 0 48.168 0.084 ;
    END
  END b[62]
  PIN b[63]
    DIRECTION OUTPUT ;
    USE SIGNAL ;
    PORT
      LAYER M5 ;
        RECT  48.24 0 48.264 0.084 ;
    END
  END b[63]
  PIN b[64]
    DIRECTION OUTPUT ;
    USE SIGNAL ;
    PORT
      LAYER M3 ;
        RECT  40.86 0 40.878 0.037 ;
    END
  END b[64]
  PIN b[65]
    DIRECTION OUTPUT ;
    USE SIGNAL ;
    PORT
      LAYER M3 ;
        RECT  40.932 0 40.95 0.037 ;
    END
  END b[65]
  PIN b[66]
    DIRECTION OUTPUT ;
    USE SIGNAL ;
    PORT
      LAYER M3 ;
        RECT  41.004 0 41.022 0.037 ;
    END
  END b[66]
  PIN b[67]
    DIRECTION OUTPUT ;
    USE SIGNAL ;
    PORT
      LAYER M3 ;
        RECT  41.076 0 41.094 0.037 ;
    END
  END b[67]
  PIN b[68]
    DIRECTION OUTPUT ;
    USE SIGNAL ;
    PORT
      LAYER M3 ;
        RECT  41.148 0 41.166 0.037 ;
    END
  END b[68]
  PIN b[69]
    DIRECTION OUTPUT ;
    USE SIGNAL ;
    PORT
      LAYER M3 ;
        RECT  41.22 0 41.238 0.037 ;
    END
  END b[69]
  PIN b[6]
    DIRECTION OUTPUT ;
    USE SIGNAL ;
    PORT
      LAYER M5 ;
        RECT  26.64 0 26.664 0.084 ;
    END
  END b[6]
  PIN b[70]
    DIRECTION OUTPUT ;
    USE SIGNAL ;
    PORT
      LAYER M3 ;
        RECT  41.292 0 41.31 0.037 ;
    END
  END b[70]
  PIN b[71]
    DIRECTION OUTPUT ;
    USE SIGNAL ;
    PORT
      LAYER M3 ;
        RECT  41.364 0 41.382 0.037 ;
    END
  END b[71]
  PIN b[72]
    DIRECTION OUTPUT ;
    USE SIGNAL ;
    PORT
      LAYER M3 ;
        RECT  41.436 0 41.454 0.037 ;
    END
  END b[72]
  PIN b[73]
    DIRECTION OUTPUT ;
    USE SIGNAL ;
    PORT
      LAYER M3 ;
        RECT  41.508 0 41.526 0.037 ;
    END
  END b[73]
  PIN b[74]
    DIRECTION OUTPUT ;
    USE SIGNAL ;
    PORT
      LAYER M3 ;
        RECT  41.58 0 41.598 0.037 ;
    END
  END b[74]
  PIN b[75]
    DIRECTION OUTPUT ;
    USE SIGNAL ;
    PORT
      LAYER M3 ;
        RECT  41.652 0 41.67 0.037 ;
    END
  END b[75]
  PIN b[76]
    DIRECTION OUTPUT ;
    USE SIGNAL ;
    PORT
      LAYER M3 ;
        RECT  41.724 0 41.742 0.037 ;
    END
  END b[76]
  PIN b[77]
    DIRECTION OUTPUT ;
    USE SIGNAL ;
    PORT
      LAYER M3 ;
        RECT  41.796 0 41.814 0.037 ;
    END
  END b[77]
  PIN b[78]
    DIRECTION OUTPUT ;
    USE SIGNAL ;
    PORT
      LAYER M3 ;
        RECT  41.868 0 41.886 0.037 ;
    END
  END b[78]
  PIN b[79]
    DIRECTION OUTPUT ;
    USE SIGNAL ;
    PORT
      LAYER M3 ;
        RECT  41.94 0 41.958 0.037 ;
    END
  END b[79]
  PIN b[7]
    DIRECTION OUTPUT ;
    USE SIGNAL ;
    PORT
      LAYER M5 ;
        RECT  26.736 0 26.76 0.084 ;
    END
  END b[7]
  PIN b[80]
    DIRECTION OUTPUT ;
    USE SIGNAL ;
    PORT
      LAYER M3 ;
        RECT  42.012 0 42.03 0.037 ;
    END
  END b[80]
  PIN b[81]
    DIRECTION OUTPUT ;
    USE SIGNAL ;
    PORT
      LAYER M3 ;
        RECT  42.084 0 42.102 0.037 ;
    END
  END b[81]
  PIN b[82]
    DIRECTION OUTPUT ;
    USE SIGNAL ;
    PORT
      LAYER M3 ;
        RECT  42.156 0 42.174 0.037 ;
    END
  END b[82]
  PIN b[83]
    DIRECTION OUTPUT ;
    USE SIGNAL ;
    PORT
      LAYER M3 ;
        RECT  42.228 0 42.246 0.037 ;
    END
  END b[83]
  PIN b[84]
    DIRECTION OUTPUT ;
    USE SIGNAL ;
    PORT
      LAYER M3 ;
        RECT  42.3 0 42.318 0.037 ;
    END
  END b[84]
  PIN b[85]
    DIRECTION OUTPUT ;
    USE SIGNAL ;
    PORT
      LAYER M3 ;
        RECT  42.372 0 42.39 0.037 ;
    END
  END b[85]
  PIN b[86]
    DIRECTION OUTPUT ;
    USE SIGNAL ;
    PORT
      LAYER M3 ;
        RECT  42.444 0 42.462 0.037 ;
    END
  END b[86]
  PIN b[87]
    DIRECTION OUTPUT ;
    USE SIGNAL ;
    PORT
      LAYER M3 ;
        RECT  42.516 0 42.534 0.037 ;
    END
  END b[87]
  PIN b[88]
    DIRECTION OUTPUT ;
    USE SIGNAL ;
    PORT
      LAYER M3 ;
        RECT  42.588 0 42.606 0.037 ;
    END
  END b[88]
  PIN b[89]
    DIRECTION OUTPUT ;
    USE SIGNAL ;
    PORT
      LAYER M3 ;
        RECT  42.66 0 42.678 0.037 ;
    END
  END b[89]
  PIN b[8]
    DIRECTION OUTPUT ;
    USE SIGNAL ;
    PORT
      LAYER M5 ;
        RECT  26.832 0 26.856 0.084 ;
    END
  END b[8]
  PIN b[90]
    DIRECTION OUTPUT ;
    USE SIGNAL ;
    PORT
      LAYER M3 ;
        RECT  42.732 0 42.75 0.037 ;
    END
  END b[90]
  PIN b[91]
    DIRECTION OUTPUT ;
    USE SIGNAL ;
    PORT
      LAYER M3 ;
        RECT  42.804 0 42.822 0.037 ;
    END
  END b[91]
  PIN b[92]
    DIRECTION OUTPUT ;
    USE SIGNAL ;
    PORT
      LAYER M3 ;
        RECT  42.876 0 42.894 0.037 ;
    END
  END b[92]
  PIN b[93]
    DIRECTION OUTPUT ;
    USE SIGNAL ;
    PORT
      LAYER M3 ;
        RECT  42.948 0 42.966 0.037 ;
    END
  END b[93]
  PIN b[94]
    DIRECTION OUTPUT ;
    USE SIGNAL ;
    PORT
      LAYER M3 ;
        RECT  43.02 0 43.038 0.037 ;
    END
  END b[94]
  PIN b[95]
    DIRECTION OUTPUT ;
    USE SIGNAL ;
    PORT
      LAYER M3 ;
        RECT  43.092 0 43.11 0.037 ;
    END
  END b[95]
  PIN b[96]
    DIRECTION OUTPUT ;
    USE SIGNAL ;
    PORT
      LAYER M3 ;
        RECT  19.548 0 19.566 0.037 ;
    END
  END b[96]
  PIN b[97]
    DIRECTION OUTPUT ;
    USE SIGNAL ;
    PORT
      LAYER M3 ;
        RECT  19.62 0 19.638 0.037 ;
    END
  END b[97]
  PIN b[98]
    DIRECTION OUTPUT ;
    USE SIGNAL ;
    PORT
      LAYER M3 ;
        RECT  19.692 0 19.71 0.037 ;
    END
  END b[98]
  PIN b[99]
    DIRECTION OUTPUT ;
    USE SIGNAL ;
    PORT
      LAYER M3 ;
        RECT  19.764 0 19.782 0.037 ;
    END
  END b[99]
  PIN b[9]
    DIRECTION OUTPUT ;
    USE SIGNAL ;
    PORT
      LAYER M5 ;
        RECT  26.928 0 26.952 0.084 ;
    END
  END b[9]
  PIN ck
    DIRECTION INPUT ;
    USE SIGNAL ;
    PORT
      LAYER M4 ;
        RECT  64.692 13.68 64.776 13.704 ;
    END
  END ck
  PIN ckf
    DIRECTION INPUT ;
    USE SIGNAL ;
    PORT
      LAYER M4 ;
        RECT  64.692 13.776 64.776 13.8 ;
    END
  END ckf
  PIN ea
    DIRECTION INPUT ;
    USE SIGNAL ;
    PORT
      LAYER M3 ;
        RECT  23.868 30.179 23.886 30.216 ;
    END
  END ea
  PIN fault
    DIRECTION OUTPUT ;
    USE SIGNAL ;
    PORT
      LAYER M4 ;
        RECT  64.692 13.872 64.776 13.896 ;
    END
  END fault
  PIN k0
    DIRECTION INPUT ;
    USE SIGNAL ;
    PORT
      LAYER M4 ;
        RECT  64.692 13.968 64.776 13.992 ;
    END
  END k0
  PIN k1
    DIRECTION INPUT ;
    USE SIGNAL ;
    PORT
      LAYER M4 ;
        RECT  64.692 14.064 64.776 14.088 ;
    END
  END k1
  PIN k2
    DIRECTION INPUT ;
    USE SIGNAL ;
    PORT
      LAYER M4 ;
        RECT  64.692 14.16 64.776 14.184 ;
    END
  END k2
  PIN rs
    DIRECTION INPUT ;
    USE SIGNAL ;
    PORT
      LAYER M4 ;
        RECT  64.692 14.256 64.776 14.28 ;
    END
  END rs
  PIN tie_hi
    DIRECTION OUTPUT ;
    USE SIGNAL ;
    PORT
      LAYER M4 ;
        RECT  64.692 14.352 64.776 14.376 ;
    END
  END tie_hi
  PIN tie_lo
    DIRECTION OUTPUT ;
    USE SIGNAL ;
    PORT
      LAYER M4 ;
        RECT  64.692 14.448 64.776 14.472 ;
    END
  END tie_lo
  PIN VDD
    DIRECTION INOUT ;
    USE POWER ;
    PORT
      LAYER M5 ;
        RECT  61.992 2.151 62.112 27.833 ;
        RECT  59.292 2.151 59.412 27.833 ;
        RECT  56.592 2.151 56.712 27.833 ;
        RECT  53.892 2.151 54.012 27.833 ;
        RECT  51.192 2.151 51.312 27.833 ;
        RECT  48.492 2.151 48.612 27.833 ;
        RECT  45.792 2.151 45.912 27.833 ;
        RECT  43.092 2.151 43.212 27.833 ;
        RECT  40.392 2.151 40.512 27.833 ;
        RECT  37.692 2.151 37.812 27.833 ;
        RECT  34.992 2.151 35.112 27.833 ;
        RECT  32.292 2.151 32.412 27.833 ;
        RECT  29.592 2.151 29.712 27.833 ;
        RECT  26.892 2.151 27.012 27.833 ;
        RECT  24.192 2.151 24.312 27.833 ;
        RECT  21.492 2.151 21.612 27.833 ;
        RECT  18.792 2.151 18.912 27.833 ;
        RECT  16.092 2.151 16.212 27.833 ;
        RECT  13.392 2.151 13.512 27.833 ;
        RECT  10.692 2.151 10.812 27.833 ;
        RECT  7.992 2.151 8.112 27.833 ;
        RECT  5.292 2.151 5.412 27.833 ;
        RECT  2.592 2.151 2.712 27.833 ;
    END
  END VDD
  PIN VSS
    DIRECTION INOUT ;
    USE GROUND ;
    PORT
      LAYER M5 ;
        RECT  61.8 2.137 61.92 27.819 ;
        RECT  59.1 2.137 59.22 27.819 ;
        RECT  56.4 2.137 56.52 27.819 ;
        RECT  53.7 2.137 53.82 27.819 ;
        RECT  51 2.137 51.12 27.819 ;
        RECT  48.3 2.137 48.42 27.819 ;
        RECT  45.6 2.137 45.72 27.819 ;
        RECT  42.9 2.137 43.02 27.819 ;
        RECT  40.2 2.137 40.32 27.819 ;
        RECT  37.5 2.137 37.62 27.819 ;
        RECT  34.8 2.137 34.92 27.819 ;
        RECT  32.1 2.137 32.22 27.819 ;
        RECT  29.4 2.137 29.52 27.819 ;
        RECT  26.7 2.137 26.82 27.819 ;
        RECT  24 2.137 24.12 27.819 ;
        RECT  21.3 2.137 21.42 27.819 ;
        RECT  18.6 2.137 18.72 27.819 ;
        RECT  15.9 2.137 16.02 27.819 ;
        RECT  13.2 2.137 13.32 27.819 ;
        RECT  10.5 2.137 10.62 27.819 ;
        RECT  7.8 2.137 7.92 27.819 ;
        RECT  5.1 2.137 5.22 27.819 ;
        RECT  2.4 2.137 2.52 27.819 ;
    END
  END VSS
  # OT_OBS_CLOSED layer=M5 d_um=1.536 added=104
  OBS
    LAYER RVTN ;
     RECT  2.16 2.16 62.586 2.295 ;
     RECT  2.16 2.565 62.586 2.835 ;
     RECT  2.16 3.105 62.586 3.375 ;
     RECT  2.16 3.645 62.586 3.915 ;
     RECT  2.16 4.185 62.586 4.455 ;
     RECT  2.16 4.725 62.586 4.995 ;
     RECT  2.16 5.265 62.586 5.535 ;
     RECT  2.16 5.805 62.586 6.075 ;
     RECT  2.16 6.345 62.586 6.615 ;
     RECT  2.16 6.885 62.586 7.155 ;
     RECT  2.16 7.425 62.586 7.695 ;
     RECT  2.16 7.965 62.586 8.235 ;
     RECT  2.16 8.505 62.586 8.775 ;
     RECT  2.16 9.045 62.586 9.315 ;
     RECT  2.16 9.585 62.586 9.855 ;
     RECT  2.16 10.125 62.586 10.395 ;
     RECT  2.16 10.665 62.586 10.935 ;
     RECT  2.16 11.205 62.586 11.475 ;
     RECT  2.16 11.745 62.586 12.015 ;
     RECT  2.16 12.285 62.586 12.555 ;
     RECT  2.16 12.825 62.586 13.095 ;
     RECT  2.16 13.365 62.586 13.635 ;
     RECT  2.16 13.905 62.586 14.175 ;
     RECT  2.16 14.445 62.586 14.715 ;
     RECT  2.16 14.985 62.586 15.255 ;
     RECT  2.16 15.525 62.586 15.795 ;
     RECT  2.16 16.065 62.586 16.335 ;
     RECT  2.16 16.605 62.586 16.875 ;
     RECT  2.16 17.145 62.586 17.415 ;
     RECT  2.16 17.685 62.586 17.955 ;
     RECT  2.16 18.225 62.586 18.495 ;
     RECT  2.16 18.765 62.586 19.035 ;
     RECT  2.16 19.305 62.586 19.575 ;
     RECT  2.16 19.845 62.586 20.115 ;
     RECT  2.16 20.385 62.586 20.655 ;
     RECT  2.16 20.925 62.586 21.195 ;
     RECT  2.16 21.465 62.586 21.735 ;
     RECT  2.16 22.005 62.586 22.275 ;
     RECT  2.16 22.545 62.586 22.815 ;
     RECT  2.16 23.085 62.586 23.355 ;
     RECT  2.16 23.625 62.586 23.895 ;
     RECT  2.16 24.165 62.586 24.435 ;
     RECT  2.16 24.705 62.586 24.975 ;
     RECT  2.16 25.245 62.586 25.515 ;
     RECT  2.16 25.785 62.586 26.055 ;
     RECT  2.16 26.325 62.586 26.595 ;
     RECT  2.16 26.865 62.586 27.135 ;
     RECT  2.16 27.405 62.586 27.675 ;
    LAYER RVTP ;
     RECT  2.16 2.295 62.586 2.565 ;
     RECT  2.16 2.835 62.586 3.105 ;
     RECT  2.16 3.375 62.586 3.645 ;
     RECT  2.16 3.915 62.586 4.185 ;
     RECT  2.16 4.455 62.586 4.725 ;
     RECT  2.16 4.995 62.586 5.265 ;
     RECT  2.16 5.535 62.586 5.805 ;
     RECT  2.16 6.075 62.586 6.345 ;
     RECT  2.16 6.615 62.586 6.885 ;
     RECT  2.16 7.155 62.586 7.425 ;
     RECT  2.16 7.695 62.586 7.965 ;
     RECT  2.16 8.235 62.586 8.505 ;
     RECT  2.16 8.775 62.586 9.045 ;
     RECT  2.16 9.315 62.586 9.585 ;
     RECT  2.16 9.855 62.586 10.125 ;
     RECT  2.16 10.395 62.586 10.665 ;
     RECT  2.16 10.935 62.586 11.205 ;
     RECT  2.16 11.475 62.586 11.745 ;
     RECT  2.16 12.015 62.586 12.285 ;
     RECT  2.16 12.555 62.586 12.825 ;
     RECT  2.16 13.095 62.586 13.365 ;
     RECT  2.16 13.635 62.586 13.905 ;
     RECT  2.16 14.175 62.586 14.445 ;
     RECT  2.16 14.715 62.586 14.985 ;
     RECT  2.16 15.255 62.586 15.525 ;
     RECT  2.16 15.795 62.586 16.065 ;
     RECT  2.16 16.335 62.586 16.605 ;
     RECT  2.16 16.875 62.586 17.145 ;
     RECT  2.16 17.415 62.586 17.685 ;
     RECT  2.16 17.955 62.586 18.225 ;
     RECT  2.16 18.495 62.586 18.765 ;
     RECT  2.16 19.035 62.586 19.305 ;
     RECT  2.16 19.575 62.586 19.845 ;
     RECT  2.16 20.115 62.586 20.385 ;
     RECT  2.16 20.655 62.586 20.925 ;
     RECT  2.16 21.195 62.586 21.465 ;
     RECT  2.16 21.735 62.586 22.005 ;
     RECT  2.16 22.275 62.586 22.545 ;
     RECT  2.16 22.815 62.586 23.085 ;
     RECT  2.16 23.355 62.586 23.625 ;
     RECT  2.16 23.895 62.586 24.165 ;
     RECT  2.16 24.435 62.586 24.705 ;
     RECT  2.16 24.975 62.586 25.245 ;
     RECT  2.16 25.515 62.586 25.785 ;
     RECT  2.16 26.055 62.586 26.325 ;
     RECT  2.16 26.595 62.586 26.865 ;
     RECT  2.16 27.135 62.586 27.405 ;
     RECT  2.16 27.675 62.586 27.81 ;
    LAYER M1 ;
     RECT  2.16 2.151 62.586 27.819 ;
    LAYER M2 ;
     RECT  2.16 2.151 17.671 27.819 ;
     RECT  17.671 2.106 18.779 27.819 ;
     RECT  18.779 2.151 19.795 27.819 ;
     RECT  19.435 0.036 20.047 0.054 ;
     RECT  19.795 1.728 20.435 27.819 ;
     RECT  20.047 0.036 21.127 0.126 ;
     RECT  21.127 0.036 21.227 0.279 ;
     RECT  20.435 2.034 21.523 27.819 ;
     RECT  21.227 0.036 21.659 0.162 ;
     RECT  21.659 0.036 21.875 0.126 ;
     RECT  21.875 0.108 22.055 0.126 ;
     RECT  21.523 1.962 23.027 27.819 ;
     RECT  23.027 2.106 23.351 27.819 ;
     RECT  23.351 2.151 23.971 27.819 ;
     RECT  23.971 2.151 24.223 27.864 ;
     RECT  24.223 2.151 24.295 27.9 ;
     RECT  24.295 2.151 24.431 27.972 ;
     RECT  24.431 2.151 24.971 27.936 ;
     RECT  24.871 30.114 25.231 30.132 ;
     RECT  25.231 30.114 25.375 30.168 ;
     RECT  25.375 30.006 25.547 30.168 ;
     RECT  25.547 30.078 25.583 30.168 ;
     RECT  25.583 30.078 25.619 30.132 ;
     RECT  24.971 2.151 27.463 27.9 ;
     RECT  25.619 30.114 27.851 30.132 ;
     RECT  27.463 2.106 28.003 27.9 ;
     RECT  27.823 0.531 28.579 0.549 ;
     RECT  28.003 2.07 29.191 27.9 ;
     RECT  28.579 0.486 29.327 0.549 ;
     RECT  29.191 1.998 30.011 27.9 ;
     RECT  30.011 2.034 30.299 27.9 ;
     RECT  29.327 0.531 30.911 0.549 ;
     RECT  30.299 2.034 31.019 27.819 ;
     RECT  31.019 2.106 32.999 27.819 ;
     RECT  32.999 2.151 34.627 27.819 ;
     RECT  34.627 2.106 36.067 27.819 ;
     RECT  35.851 30.15 36.355 30.168 ;
     RECT  36.067 2.106 36.419 27.864 ;
     RECT  36.355 30.006 36.995 30.168 ;
     RECT  36.995 30.006 37.355 30.024 ;
     RECT  36.419 2.106 37.399 27.819 ;
     RECT  37.399 2.07 37.687 27.819 ;
     RECT  37.687 2.07 37.859 27.9 ;
     RECT  37.903 30.15 38.263 30.168 ;
     RECT  38.263 30.114 38.867 30.168 ;
     RECT  38.867 30.15 39.515 30.168 ;
     RECT  37.859 2.07 40.819 27.819 ;
     RECT  40.819 1.728 41.459 27.819 ;
     RECT  41.359 0.036 41.503 0.054 ;
     RECT  41.459 2.07 41.531 27.819 ;
     RECT  41.503 0.036 41.611 0.126 ;
     RECT  41.611 0.036 42.475 0.198 ;
     RECT  41.531 2.106 42.611 27.819 ;
     RECT  42.511 30.006 42.611 30.024 ;
     RECT  42.611 2.151 42.655 27.819 ;
     RECT  42.475 0.036 43.367 0.279 ;
     RECT  43.367 0.072 43.619 0.279 ;
     RECT  43.619 0.072 43.907 0.126 ;
     RECT  42.691 30.186 43.979 30.204 ;
     RECT  42.655 2.151 44.159 27.936 ;
     RECT  43.907 0.108 44.555 0.126 ;
     RECT  44.159 2.151 44.879 27.864 ;
     RECT  44.879 2.151 46.903 27.819 ;
     RECT  47.011 0.531 47.767 0.549 ;
     RECT  46.903 2.106 47.839 27.819 ;
     RECT  47.839 1.998 49.271 27.819 ;
     RECT  49.271 2.07 49.415 27.819 ;
     RECT  47.767 0.261 49.631 0.549 ;
     RECT  49.631 0.261 49.667 0.324 ;
     RECT  49.667 0.261 49.847 0.279 ;
     RECT  49.415 2.106 50.711 27.819 ;
     RECT  50.711 2.151 62.586 27.819 ;
     RECT  62.586 13.644 62.807 14.634 ;
     RECT  62.807 13.806 63.311 14.634 ;
     RECT  63.311 14.184 63.851 14.238 ;
     RECT  63.851 14.184 63.887 14.202 ;
    LAYER M3 ;
     RECT  19.566 0.012 19.62 0.031 ;
     RECT  19.638 0.012 19.692 0.031 ;
     RECT  19.71 0.012 19.764 0.031 ;
     RECT  19.782 0.012 19.836 0.031 ;
     RECT  19.854 0.012 19.908 0.031 ;
     RECT  19.926 0.012 19.98 0.031 ;
     RECT  19.998 0.012 20.052 0.031 ;
     RECT  20.07 0.012 20.124 0.031 ;
     RECT  20.142 0.012 20.196 0.031 ;
     RECT  20.214 0.012 20.268 0.031 ;
     RECT  20.286 0.012 20.34 0.031 ;
     RECT  20.358 0.012 20.412 0.031 ;
     RECT  20.43 0.012 20.484 0.031 ;
     RECT  20.502 0.012 20.556 0.031 ;
     RECT  20.574 0.012 20.628 0.031 ;
     RECT  20.646 0.012 20.7 0.031 ;
     RECT  20.718 0.012 20.772 0.031 ;
     RECT  20.79 0.012 20.844 0.031 ;
     RECT  20.862 0.012 20.916 0.031 ;
     RECT  20.934 0.012 20.988 0.031 ;
     RECT  21.006 0.012 21.06 0.031 ;
     RECT  21.078 0.012 21.132 0.031 ;
     RECT  21.15 0.012 21.204 0.031 ;
     RECT  21.222 0.012 21.276 0.031 ;
     RECT  21.294 0.012 21.348 0.031 ;
     RECT  21.366 0.012 21.42 0.031 ;
     RECT  21.438 0.012 21.492 0.031 ;
     RECT  21.51 0.012 21.564 0.031 ;
     RECT  21.582 0.012 21.636 0.031 ;
     RECT  21.654 0.012 21.708 0.031 ;
     RECT  21.726 0.012 21.78 0.031 ;
     RECT  40.878 0.012 40.932 0.031 ;
     RECT  40.95 0.012 41.004 0.031 ;
     RECT  41.022 0.012 41.076 0.031 ;
     RECT  41.094 0.012 41.148 0.031 ;
     RECT  41.166 0.012 41.22 0.031 ;
     RECT  41.238 0.012 41.292 0.031 ;
     RECT  41.31 0.012 41.364 0.031 ;
     RECT  41.382 0.012 41.436 0.031 ;
     RECT  41.454 0.012 41.508 0.031 ;
     RECT  41.526 0.012 41.58 0.031 ;
     RECT  41.598 0.012 41.652 0.031 ;
     RECT  41.67 0.012 41.724 0.031 ;
     RECT  41.742 0.012 41.796 0.031 ;
     RECT  41.814 0.012 41.868 0.031 ;
     RECT  41.886 0.012 41.94 0.031 ;
     RECT  41.958 0.012 42.012 0.031 ;
     RECT  42.03 0.012 42.084 0.031 ;
     RECT  42.102 0.012 42.156 0.031 ;
     RECT  42.174 0.012 42.228 0.031 ;
     RECT  42.246 0.012 42.3 0.031 ;
     RECT  42.318 0.012 42.372 0.031 ;
     RECT  42.39 0.012 42.444 0.031 ;
     RECT  42.462 0.012 42.516 0.031 ;
     RECT  42.534 0.012 42.588 0.031 ;
     RECT  42.606 0.012 42.66 0.031 ;
     RECT  42.678 0.012 42.732 0.031 ;
     RECT  42.75 0.012 42.804 0.031 ;
     RECT  42.822 0.012 42.876 0.031 ;
     RECT  42.894 0.012 42.948 0.031 ;
     RECT  42.966 0.012 43.02 0.031 ;
     RECT  43.038 0.012 43.092 0.031 ;
     RECT  19.44 0.031 19.548 0.037 ;
     RECT  19.566 0.031 19.62 0.037 ;
     RECT  19.638 0.031 19.692 0.037 ;
     RECT  19.71 0.031 19.764 0.037 ;
     RECT  19.782 0.031 19.836 0.037 ;
     RECT  19.854 0.031 19.908 0.037 ;
     RECT  19.926 0.031 19.98 0.037 ;
     RECT  19.998 0.031 20.052 0.037 ;
     RECT  20.07 0.031 20.124 0.037 ;
     RECT  20.142 0.031 20.196 0.037 ;
     RECT  20.214 0.031 20.268 0.037 ;
     RECT  20.286 0.031 20.34 0.037 ;
     RECT  20.358 0.031 20.412 0.037 ;
     RECT  20.43 0.031 20.484 0.037 ;
     RECT  20.502 0.031 20.556 0.037 ;
     RECT  20.574 0.031 20.628 0.037 ;
     RECT  20.646 0.031 20.7 0.037 ;
     RECT  20.718 0.031 20.772 0.037 ;
     RECT  20.79 0.031 20.844 0.037 ;
     RECT  20.862 0.031 20.916 0.037 ;
     RECT  20.934 0.031 20.988 0.037 ;
     RECT  21.006 0.031 21.06 0.037 ;
     RECT  21.078 0.031 21.132 0.037 ;
     RECT  21.15 0.031 21.204 0.037 ;
     RECT  21.222 0.031 21.276 0.037 ;
     RECT  21.294 0.031 21.348 0.037 ;
     RECT  21.366 0.031 21.42 0.037 ;
     RECT  21.438 0.031 21.492 0.037 ;
     RECT  21.51 0.031 21.564 0.037 ;
     RECT  21.582 0.031 21.636 0.037 ;
     RECT  21.654 0.031 21.708 0.037 ;
     RECT  21.726 0.031 21.78 0.037 ;
     RECT  21.798 0.031 21.87 0.037 ;
     RECT  19.44 0.037 21.87 0.043 ;
     RECT  40.878 0.031 40.932 0.037 ;
     RECT  40.95 0.031 41.004 0.037 ;
     RECT  41.022 0.031 41.076 0.037 ;
     RECT  41.094 0.031 41.148 0.037 ;
     RECT  41.166 0.031 41.22 0.037 ;
     RECT  41.238 0.031 41.292 0.037 ;
     RECT  41.31 0.031 41.364 0.037 ;
     RECT  41.382 0.031 41.436 0.037 ;
     RECT  41.454 0.031 41.508 0.037 ;
     RECT  41.526 0.031 41.58 0.037 ;
     RECT  41.598 0.031 41.652 0.037 ;
     RECT  41.67 0.031 41.724 0.037 ;
     RECT  41.742 0.031 41.796 0.037 ;
     RECT  41.814 0.031 41.868 0.037 ;
     RECT  41.886 0.031 41.94 0.037 ;
     RECT  41.958 0.031 42.012 0.037 ;
     RECT  42.03 0.031 42.084 0.037 ;
     RECT  42.102 0.031 42.156 0.037 ;
     RECT  42.174 0.031 42.228 0.037 ;
     RECT  42.246 0.031 42.3 0.037 ;
     RECT  42.318 0.031 42.372 0.037 ;
     RECT  42.39 0.031 42.444 0.037 ;
     RECT  42.462 0.031 42.516 0.037 ;
     RECT  42.534 0.031 42.588 0.037 ;
     RECT  42.606 0.031 42.66 0.037 ;
     RECT  42.678 0.031 42.732 0.037 ;
     RECT  42.75 0.031 42.804 0.037 ;
     RECT  42.822 0.031 42.876 0.037 ;
     RECT  42.894 0.031 42.948 0.037 ;
     RECT  42.966 0.031 43.02 0.037 ;
     RECT  43.038 0.031 43.092 0.037 ;
     RECT  43.11 0.031 43.362 0.037 ;
     RECT  40.86 0.037 43.362 0.067 ;
     RECT  40.86 0.067 43.902 0.103 ;
     RECT  45.144 0.091 45.378 0.103 ;
     RECT  46.296 0.091 46.854 0.139 ;
     RECT  48.96 0.091 48.978 0.139 ;
     RECT  46.296 0.139 47.394 0.235 ;
     RECT  48.96 0.139 49.302 0.256 ;
     RECT  50.184 0.187 50.202 0.256 ;
     RECT  46.296 0.235 47.79 0.283 ;
     RECT  48.96 0.256 50.202 0.283 ;
     RECT  46.296 0.283 50.202 0.284 ;
     RECT  48.276 0.284 50.202 0.329 ;
     RECT  26.064 0.091 28.602 0.481 ;
     RECT  26.064 0.481 29.322 0.509 ;
     RECT  40.86 0.103 45.378 0.523 ;
     RECT  46.296 0.284 47.394 0.523 ;
     RECT  29.232 0.509 29.322 0.554 ;
     RECT  29.232 0.554 29.25 1.723 ;
     RECT  40.86 0.523 47.394 1.723 ;
     RECT  48.96 0.329 50.202 1.723 ;
     RECT  26.064 0.509 28.206 1.771 ;
     RECT  29.232 1.723 29.322 1.771 ;
     RECT  26.064 1.771 29.322 1.819 ;
     RECT  40.824 1.723 47.394 1.819 ;
     RECT  48.456 1.723 50.202 1.819 ;
     RECT  26.064 1.819 29.79 1.867 ;
     RECT  30.888 0.526 30.906 1.867 ;
     RECT  19.44 0.043 22.374 1.957 ;
     RECT  26.064 1.867 30.906 2.029 ;
     RECT  19.44 1.957 23.022 2.101 ;
     RECT  40.824 1.819 50.202 2.101 ;
     RECT  18.756 2.101 23.346 2.143 ;
     RECT  34.632 2.101 34.65 2.143 ;
     RECT  37.404 2.065 37.422 2.143 ;
     RECT  40.824 2.101 50.706 2.143 ;
     RECT  26.064 2.029 31.014 2.219 ;
     RECT  26.064 2.219 30.906 2.227 ;
     RECT  15.12 2.191 15.138 2.263 ;
     RECT  15.915 2.143 16.005 2.263 ;
     RECT  53.715 2.143 53.805 2.263 ;
     RECT  36.432 2.263 36.45 2.335 ;
     RECT  13.215 2.143 13.305 2.371 ;
     RECT  14.796 2.263 16.005 2.371 ;
     RECT  25.812 2.227 30.906 2.371 ;
     RECT  36 2.335 36.45 2.371 ;
     RECT  37.404 2.143 37.605 2.371 ;
     RECT  40.215 2.143 51.105 2.371 ;
     RECT  2.415 2.143 2.505 2.413 ;
     RECT  5.115 2.143 5.205 2.413 ;
     RECT  7.815 2.143 7.905 2.413 ;
     RECT  10.515 2.143 10.605 2.413 ;
     RECT  12.96 2.371 13.305 2.413 ;
     RECT  18.615 2.143 24.105 2.413 ;
     RECT  32.115 2.143 32.205 2.413 ;
     RECT  32.976 2.101 32.994 2.413 ;
     RECT  34.632 2.143 34.905 2.413 ;
     RECT  36 2.371 37.605 2.413 ;
     RECT  39.636 2.371 51.105 2.413 ;
     RECT  53.136 2.263 53.805 2.413 ;
     RECT  56.415 2.143 56.505 2.413 ;
     RECT  59.115 2.143 59.205 2.413 ;
     RECT  61.815 2.143 61.905 2.413 ;
     RECT  36 2.413 37.797 2.488 ;
     RECT  38.772 2.101 38.862 2.488 ;
     RECT  25.488 2.371 30.906 2.497 ;
     RECT  25.38 2.497 30.906 2.533 ;
     RECT  12.96 2.413 13.497 2.569 ;
     RECT  14.796 2.371 16.254 2.569 ;
     RECT  17.676 2.101 17.694 2.569 ;
     RECT  34.632 2.413 35.097 2.569 ;
     RECT  11.988 2.569 13.497 2.605 ;
     RECT  14.796 2.569 17.694 2.605 ;
     RECT  36 2.488 38.862 2.632 ;
     RECT  39.636 2.413 51.297 2.632 ;
     RECT  11.988 2.605 13.95 2.635 ;
     RECT  14.76 2.605 17.694 2.635 ;
     RECT  10.515 2.413 10.797 2.641 ;
     RECT  11.988 2.635 17.694 2.641 ;
     RECT  18.615 2.413 24.297 2.641 ;
     RECT  25.308 2.533 30.906 2.641 ;
     RECT  9.072 2.641 10.797 2.717 ;
     RECT  9.648 2.717 10.797 2.759 ;
     RECT  9.684 2.759 10.797 2.767 ;
     RECT  11.664 2.641 17.694 2.767 ;
     RECT  34.344 2.569 35.097 2.767 ;
     RECT  36 2.632 51.297 2.767 ;
     RECT  9.684 2.767 17.694 2.875 ;
     RECT  18.615 2.641 30.906 2.875 ;
     RECT  9.684 2.875 30.906 3.065 ;
     RECT  9.756 3.065 30.906 3.109 ;
     RECT  34.344 2.767 51.297 3.145 ;
     RECT  53.136 2.413 53.997 3.181 ;
     RECT  9.756 3.109 30.942 3.271 ;
     RECT  9.756 3.271 31.05 3.343 ;
     RECT  34.344 3.145 51.606 3.379 ;
     RECT  9.756 3.343 31.266 3.451 ;
     RECT  32.115 2.413 32.994 3.451 ;
     RECT  9 3.835 9.018 4.109 ;
     RECT  34.344 3.379 51.894 4.225 ;
     RECT  9.756 3.451 32.994 4.955 ;
     RECT  34.344 4.225 52.146 5.071 ;
     RECT  52.92 3.181 53.997 5.071 ;
     RECT  9.792 4.955 32.994 6.151 ;
     RECT  34.344 5.071 53.997 6.241 ;
     RECT  9.72 6.151 32.994 6.313 ;
     RECT  9.684 6.313 32.994 6.385 ;
     RECT  34.344 6.241 54.126 6.421 ;
     RECT  34.344 6.421 54.234 6.961 ;
     RECT  55.152 6.547 55.17 6.961 ;
     RECT  9.684 6.385 33.066 7.151 ;
     RECT  56.415 2.413 56.697 7.231 ;
     RECT  34.344 6.961 55.17 7.321 ;
     RECT  56.34 7.231 56.697 7.349 ;
     RECT  34.128 7.321 55.314 7.393 ;
     RECT  9.72 7.151 33.066 7.501 ;
     RECT  34.02 7.393 55.314 7.501 ;
     RECT  9.72 7.501 33.174 7.619 ;
     RECT  34.02 7.501 55.566 7.619 ;
     RECT  34.02 7.619 55.494 8.239 ;
     RECT  9.9 7.619 33.174 8.311 ;
     RECT  33.948 8.239 55.494 8.311 ;
     RECT  9.9 8.311 55.494 8.429 ;
     RECT  9.756 8.437 9.774 8.477 ;
     RECT  10.515 8.429 55.494 8.477 ;
     RECT  11.664 8.477 55.494 8.671 ;
     RECT  11.664 8.671 55.53 8.851 ;
     RECT  56.415 7.349 56.697 8.851 ;
     RECT  11.664 8.851 56.697 9.005 ;
     RECT  54.756 9.005 56.697 9.077 ;
     RECT  11.664 9.005 53.997 9.653 ;
     RECT  54.756 9.077 55.602 10.291 ;
     RECT  56.415 9.077 56.697 10.291 ;
     RECT  12.528 9.653 53.997 10.697 ;
     RECT  11.664 9.653 11.754 10.975 ;
     RECT  12.528 10.697 17.73 10.975 ;
     RECT  18.504 10.697 53.997 11.281 ;
     RECT  54.756 10.291 56.697 11.281 ;
     RECT  11.664 10.975 17.73 11.785 ;
     RECT  18.504 11.281 56.697 11.785 ;
     RECT  11.664 11.785 56.697 11.981 ;
     RECT  18.504 11.981 56.697 12.829 ;
     RECT  11.664 11.981 17.73 13.099 ;
     RECT  18.504 12.829 56.754 13.099 ;
     RECT  11.664 13.099 56.754 13.289 ;
     RECT  11.664 13.289 56.697 13.559 ;
     RECT  61.815 2.413 62.097 13.639 ;
     RECT  15.84 13.559 56.697 13.667 ;
     RECT  61.815 13.639 62.802 13.801 ;
     RECT  15.84 13.667 33.858 13.829 ;
     RECT  59.115 2.413 59.397 14.071 ;
     RECT  60.516 13.981 60.534 14.071 ;
     RECT  11.664 13.559 15.066 14.099 ;
     RECT  61.815 13.801 63.306 14.155 ;
     RECT  34.596 13.667 56.697 14.171 ;
     RECT  61.815 14.155 63.882 14.207 ;
     RECT  49.356 14.171 56.697 14.215 ;
     RECT  59.115 14.071 60.534 14.279 ;
     RECT  61.815 14.207 63.846 14.381 ;
     RECT  61.815 14.381 63.306 14.441 ;
     RECT  59.115 14.279 60.426 14.449 ;
     RECT  58.824 14.449 60.426 14.477 ;
     RECT  61.815 14.441 62.19 14.513 ;
     RECT  15.915 13.829 33.858 14.521 ;
     RECT  34.596 14.171 48.597 14.521 ;
     RECT  49.356 14.215 57.33 14.521 ;
     RECT  58.824 14.477 59.85 14.521 ;
     RECT  63.288 14.441 63.306 14.639 ;
     RECT  49.356 14.521 57.762 14.683 ;
     RECT  58.716 14.521 59.85 14.683 ;
     RECT  49.356 14.683 59.85 14.783 ;
     RECT  15.915 14.521 48.597 14.923 ;
     RECT  49.356 14.783 59.397 14.923 ;
     RECT  15.915 14.923 59.397 15.061 ;
     RECT  15.876 15.061 59.397 15.089 ;
     RECT  15.876 15.089 57.87 15.245 ;
     RECT  58.824 15.089 59.397 15.287 ;
     RECT  15.915 15.245 57.87 15.293 ;
     RECT  15.915 15.293 57.546 15.323 ;
     RECT  15.915 15.323 56.754 15.449 ;
     RECT  57.528 15.323 57.546 15.521 ;
     RECT  11.664 14.099 12.258 18.419 ;
     RECT  13.215 14.099 15.066 18.535 ;
     RECT  15.915 15.449 56.697 18.535 ;
     RECT  11.664 18.419 12.15 18.599 ;
     RECT  13.215 18.535 56.697 18.605 ;
     RECT  15.915 18.605 56.697 18.689 ;
     RECT  15.915 18.689 55.566 18.725 ;
     RECT  15.915 18.725 55.494 18.761 ;
     RECT  13.215 18.605 15.174 18.797 ;
     RECT  14.292 18.797 15.066 19.607 ;
     RECT  15.915 18.761 54.99 20.039 ;
     RECT  15.915 20.039 54.09 20.489 ;
     RECT  15.915 20.489 40.554 20.579 ;
     RECT  15.915 20.579 17.478 20.765 ;
     RECT  14.508 19.607 15.066 21.227 ;
     RECT  41.328 20.489 54.09 21.235 ;
     RECT  15.048 21.227 15.066 21.389 ;
     RECT  18.216 20.579 40.497 21.659 ;
     RECT  18.216 21.659 19.494 21.821 ;
     RECT  20.484 21.659 33.93 21.929 ;
     RECT  41.292 21.235 54.09 22.001 ;
     RECT  20.484 21.929 33.822 22.037 ;
     RECT  15.915 20.765 17.442 22.081 ;
     RECT  18.216 21.821 19.458 22.081 ;
     RECT  41.292 22.001 54.018 22.199 ;
     RECT  20.484 22.037 32.634 22.235 ;
     RECT  20.484 22.235 20.502 22.469 ;
     RECT  21.315 22.235 32.634 22.505 ;
     RECT  41.292 22.199 53.997 22.585 ;
     RECT  20.268 22.585 20.286 22.637 ;
     RECT  34.815 21.659 40.497 22.747 ;
     RECT  41.22 22.585 53.997 22.747 ;
     RECT  15.084 21.505 15.102 22.819 ;
     RECT  15.084 22.819 15.174 22.847 ;
     RECT  21.315 22.505 21.906 23.009 ;
     RECT  22.644 22.505 32.634 23.045 ;
     RECT  22.644 23.045 32.49 23.279 ;
     RECT  33.408 22.037 33.822 23.279 ;
     RECT  22.644 23.279 32.397 23.315 ;
     RECT  30.96 23.315 31.05 23.351 ;
     RECT  22.644 23.315 29.754 23.405 ;
     RECT  34.815 22.747 53.997 23.819 ;
     RECT  34.815 23.819 49.194 23.855 ;
     RECT  15.915 22.081 19.458 23.927 ;
     RECT  15.915 23.927 19.278 23.933 ;
     RECT  15.156 22.847 15.174 23.947 ;
     RECT  15.915 23.933 19.242 23.947 ;
     RECT  33.408 23.279 33.426 24.089 ;
     RECT  49.932 23.819 52.938 24.089 ;
     RECT  49.932 24.089 52.83 24.125 ;
     RECT  31.032 23.351 31.05 24.205 ;
     RECT  41.652 23.855 49.194 24.359 ;
     RECT  49.932 24.125 52.578 24.359 ;
     RECT  30.924 24.205 31.05 24.367 ;
     RECT  31.932 23.315 32.397 24.367 ;
     RECT  12.132 18.599 12.15 24.467 ;
     RECT  15.156 23.947 19.242 24.469 ;
     RECT  14.544 24.469 19.242 24.509 ;
     RECT  14.832 24.509 19.242 24.512 ;
     RECT  41.904 24.359 49.194 24.557 ;
     RECT  14.832 24.512 15.174 24.629 ;
     RECT  22.824 23.405 29.754 24.781 ;
     RECT  30.924 24.367 32.397 24.781 ;
     RECT  44.856 24.557 49.194 24.781 ;
     RECT  49.932 24.359 51.93 24.781 ;
     RECT  44.856 24.781 51.93 24.899 ;
     RECT  22.824 24.781 32.397 24.935 ;
     RECT  44.856 24.899 49.374 24.935 ;
     RECT  50.184 24.899 51.786 24.935 ;
     RECT  15.084 24.629 15.174 24.941 ;
     RECT  50.292 24.935 51.786 24.971 ;
     RECT  41.904 24.557 44.082 25.099 ;
     RECT  20.016 25.099 20.034 25.169 ;
     RECT  22.824 24.935 30.942 25.169 ;
     RECT  15.915 24.512 19.242 25.285 ;
     RECT  41.652 25.099 44.082 25.285 ;
     RECT  15.915 25.285 19.926 25.325 ;
     RECT  22.824 25.169 30.474 25.349 ;
     RECT  22.824 25.349 28.098 25.439 ;
     RECT  46.944 24.935 49.374 25.439 ;
     RECT  29.124 25.349 30.474 25.475 ;
     RECT  46.944 25.439 49.122 25.475 ;
     RECT  21.315 23.009 21.597 25.675 ;
     RECT  41.508 25.285 44.082 25.675 ;
     RECT  44.856 24.935 46.17 25.675 ;
     RECT  22.824 25.439 27.918 25.709 ;
     RECT  48.024 25.475 49.122 25.709 ;
     RECT  22.824 25.709 27.81 25.745 ;
     RECT  15.156 24.941 15.174 25.825 ;
     RECT  15.915 25.325 19.242 25.825 ;
     RECT  41.364 25.675 46.17 25.825 ;
     RECT  46.944 25.475 47.286 25.825 ;
     RECT  15.156 25.825 19.242 26.087 ;
     RECT  20.7 25.675 21.597 26.095 ;
     RECT  41.364 25.825 47.286 26.095 ;
     RECT  41.22 26.095 47.286 26.141 ;
     RECT  20.484 26.095 21.597 26.203 ;
     RECT  20.052 26.203 21.597 26.249 ;
     RECT  34.815 23.855 40.497 26.249 ;
     RECT  20.052 26.249 20.394 26.477 ;
     RECT  20.052 26.477 20.07 26.519 ;
     RECT  15.876 26.087 19.242 26.629 ;
     RECT  15.876 26.629 19.854 26.669 ;
     RECT  41.22 26.141 43.197 26.669 ;
     RECT  22.824 25.745 27.702 26.789 ;
     RECT  50.292 24.971 51.297 26.789 ;
     RECT  41.904 26.669 43.197 26.905 ;
     RECT  43.92 26.141 47.286 26.905 ;
     RECT  15.876 26.669 19.602 27.059 ;
     RECT  26.64 26.789 27.702 27.059 ;
     RECT  31.968 24.935 32.397 27.059 ;
     RECT  48.315 25.709 49.122 27.059 ;
     RECT  23.364 26.789 25.722 27.095 ;
     RECT  32.004 27.059 32.397 27.131 ;
     RECT  15.876 27.059 19.494 27.163 ;
     RECT  29.415 25.475 30.474 27.175 ;
     RECT  26.64 27.059 26.997 27.329 ;
     RECT  15.804 27.163 19.494 27.341 ;
     RECT  15.804 27.341 19.098 27.365 ;
     RECT  41.904 26.905 47.286 27.445 ;
     RECT  50.256 26.905 50.274 27.473 ;
     RECT  27.828 27.337 27.846 27.481 ;
     RECT  41.76 27.445 47.286 27.509 ;
     RECT  48.315 27.059 48.798 27.509 ;
     RECT  2.415 2.413 2.697 27.557 ;
     RECT  5.115 2.413 5.397 27.557 ;
     RECT  7.815 2.413 8.097 27.557 ;
     RECT  10.515 8.477 10.797 27.557 ;
     RECT  13.215 18.797 13.497 27.557 ;
     RECT  21.315 26.249 21.597 27.557 ;
     RECT  26.715 27.329 26.997 27.557 ;
     RECT  29.415 27.175 31.194 27.557 ;
     RECT  32.115 27.131 32.397 27.557 ;
     RECT  34.815 26.249 35.097 27.557 ;
     RECT  35.82 26.249 40.497 27.557 ;
     RECT  45.615 27.509 47.286 27.557 ;
     RECT  48.315 27.509 48.597 27.557 ;
     RECT  51.015 26.789 51.297 27.557 ;
     RECT  53.715 23.819 53.997 27.557 ;
     RECT  56.415 18.689 56.697 27.557 ;
     RECT  59.115 15.287 59.397 27.557 ;
     RECT  61.815 14.513 62.097 27.557 ;
     RECT  23.868 27.095 25.722 27.599 ;
     RECT  29.607 27.557 31.194 27.599 ;
     RECT  35.82 27.557 39.51 27.599 ;
     RECT  41.76 27.509 44.874 27.599 ;
     RECT  45.756 27.557 47.286 27.599 ;
     RECT  27.828 27.481 27.918 27.635 ;
     RECT  46.656 27.599 46.746 27.743 ;
     RECT  29.607 27.599 30.366 27.779 ;
     RECT  31.176 27.599 31.194 27.779 ;
     RECT  46.728 27.743 46.746 27.779 ;
     RECT  2.607 27.557 2.697 27.827 ;
     RECT  5.307 27.557 5.397 27.827 ;
     RECT  8.007 27.557 8.097 27.827 ;
     RECT  10.707 27.557 10.797 27.827 ;
     RECT  13.407 27.557 13.497 27.827 ;
     RECT  21.507 27.557 21.597 27.827 ;
     RECT  26.907 27.557 26.997 27.827 ;
     RECT  29.607 27.779 30.294 27.827 ;
     RECT  32.307 27.557 32.397 27.827 ;
     RECT  35.007 27.557 35.097 27.827 ;
     RECT  40.407 27.557 40.497 27.827 ;
     RECT  41.796 27.599 44.874 27.827 ;
     RECT  45.807 27.599 45.897 27.827 ;
     RECT  48.507 27.557 48.597 27.827 ;
     RECT  51.207 27.557 51.297 27.827 ;
     RECT  53.907 27.557 53.997 27.827 ;
     RECT  56.607 27.557 56.697 27.827 ;
     RECT  59.307 27.557 59.397 27.827 ;
     RECT  62.007 27.557 62.097 27.827 ;
     RECT  43.776 27.827 44.874 27.869 ;
     RECT  23.868 27.599 25.614 27.905 ;
     RECT  30.276 27.827 30.294 27.905 ;
     RECT  43.776 27.869 44.154 27.917 ;
     RECT  43.956 27.917 44.154 27.941 ;
     RECT  15.876 27.365 19.098 27.965 ;
     RECT  16.596 27.965 16.722 28.013 ;
     RECT  17.46 27.965 19.098 28.493 ;
     RECT  17.46 28.493 17.478 28.541 ;
     RECT  23.868 27.905 25.578 29.659 ;
     RECT  41.796 27.827 42.894 29.659 ;
     RECT  35.856 27.599 37.998 30.043 ;
     RECT  35.856 30.043 38.07 30.091 ;
     RECT  38.844 27.599 39.51 30.091 ;
     RECT  40.86 29.659 42.894 30.091 ;
     RECT  16.596 28.013 16.614 30.125 ;
     RECT  27.828 27.635 27.846 30.137 ;
     RECT  35.856 30.091 39.51 30.137 ;
     RECT  40.716 30.091 42.894 30.139 ;
     RECT  35.856 30.137 38.286 30.173 ;
     RECT  39.492 30.137 39.51 30.173 ;
     RECT  23.868 29.659 26.19 30.179 ;
     RECT  23.886 30.179 23.94 30.204 ;
     RECT  23.958 30.179 24.012 30.204 ;
     RECT  24.03 30.179 24.084 30.204 ;
     RECT  24.102 30.179 24.156 30.204 ;
     RECT  24.174 30.179 24.228 30.204 ;
     RECT  24.246 30.179 24.3 30.204 ;
     RECT  24.318 30.179 24.372 30.204 ;
     RECT  24.39 30.179 24.444 30.204 ;
     RECT  24.462 30.179 24.516 30.204 ;
     RECT  24.534 30.179 24.588 30.204 ;
     RECT  24.606 30.179 24.66 30.204 ;
     RECT  24.678 30.179 24.732 30.204 ;
     RECT  24.75 30.179 24.804 30.204 ;
     RECT  24.822 30.179 24.876 30.204 ;
     RECT  24.894 30.179 24.948 30.204 ;
     RECT  24.966 30.179 25.02 30.204 ;
     RECT  25.038 30.179 25.092 30.204 ;
     RECT  25.11 30.179 25.164 30.204 ;
     RECT  25.182 30.179 25.236 30.204 ;
     RECT  25.254 30.179 25.308 30.204 ;
     RECT  25.326 30.179 25.38 30.204 ;
     RECT  25.398 30.179 25.452 30.204 ;
     RECT  25.47 30.179 25.524 30.204 ;
     RECT  25.542 30.179 25.596 30.204 ;
     RECT  25.614 30.179 25.668 30.204 ;
     RECT  25.686 30.179 25.74 30.204 ;
     RECT  25.758 30.179 25.812 30.204 ;
     RECT  25.83 30.179 25.884 30.204 ;
     RECT  25.902 30.179 25.956 30.204 ;
     RECT  25.974 30.179 26.028 30.204 ;
     RECT  26.046 30.179 26.1 30.204 ;
     RECT  26.118 30.179 26.172 30.204 ;
     RECT  36.036 30.173 38.286 30.179 ;
     RECT  36.054 30.179 36.108 30.204 ;
     RECT  36.126 30.179 36.18 30.204 ;
     RECT  36.198 30.179 36.252 30.204 ;
     RECT  36.27 30.179 36.324 30.204 ;
     RECT  36.342 30.179 36.396 30.204 ;
     RECT  36.414 30.179 36.468 30.204 ;
     RECT  36.486 30.179 36.54 30.204 ;
     RECT  36.558 30.179 36.612 30.204 ;
     RECT  36.63 30.179 36.684 30.204 ;
     RECT  36.702 30.179 36.756 30.204 ;
     RECT  36.774 30.179 36.828 30.204 ;
     RECT  36.846 30.179 36.9 30.204 ;
     RECT  36.918 30.179 36.972 30.204 ;
     RECT  36.99 30.179 37.044 30.204 ;
     RECT  37.062 30.179 37.116 30.204 ;
     RECT  37.134 30.179 37.188 30.204 ;
     RECT  37.206 30.179 37.26 30.204 ;
     RECT  37.278 30.179 37.332 30.204 ;
     RECT  37.35 30.179 37.404 30.204 ;
     RECT  37.422 30.179 37.476 30.204 ;
     RECT  37.494 30.179 37.548 30.204 ;
     RECT  37.566 30.179 37.62 30.204 ;
     RECT  37.638 30.179 37.692 30.204 ;
     RECT  37.71 30.179 37.764 30.204 ;
     RECT  37.782 30.179 37.836 30.204 ;
     RECT  37.854 30.179 37.908 30.204 ;
     RECT  37.926 30.179 37.98 30.204 ;
     RECT  37.998 30.179 38.052 30.204 ;
     RECT  38.07 30.179 38.124 30.204 ;
     RECT  38.142 30.179 38.196 30.204 ;
     RECT  38.214 30.179 38.268 30.204 ;
     RECT  40.644 30.139 42.894 30.179 ;
     RECT  40.662 30.179 40.716 30.204 ;
     RECT  40.734 30.179 40.788 30.204 ;
     RECT  40.806 30.179 40.86 30.204 ;
     RECT  40.878 30.179 40.932 30.204 ;
     RECT  40.95 30.179 41.004 30.204 ;
     RECT  41.022 30.179 41.076 30.204 ;
     RECT  41.094 30.179 41.148 30.204 ;
     RECT  41.166 30.179 41.22 30.204 ;
     RECT  41.238 30.179 41.292 30.204 ;
     RECT  41.31 30.179 41.364 30.204 ;
     RECT  41.382 30.179 41.436 30.204 ;
     RECT  41.454 30.179 41.508 30.204 ;
     RECT  41.526 30.179 41.58 30.204 ;
     RECT  41.598 30.179 41.652 30.204 ;
     RECT  41.67 30.179 41.724 30.204 ;
     RECT  41.742 30.179 41.796 30.204 ;
     RECT  41.814 30.179 41.868 30.204 ;
     RECT  41.886 30.179 41.94 30.204 ;
     RECT  41.958 30.179 42.012 30.204 ;
     RECT  42.03 30.179 42.084 30.204 ;
     RECT  42.102 30.179 42.156 30.204 ;
     RECT  42.174 30.179 42.228 30.204 ;
     RECT  42.246 30.179 42.3 30.204 ;
     RECT  42.318 30.179 42.372 30.204 ;
     RECT  42.39 30.179 42.444 30.204 ;
     RECT  42.462 30.179 42.516 30.204 ;
     RECT  42.534 30.179 42.588 30.204 ;
     RECT  42.606 30.179 42.66 30.204 ;
     RECT  42.678 30.179 42.732 30.204 ;
     RECT  42.75 30.179 42.804 30.204 ;
     RECT  42.822 30.179 42.876 30.204 ;
     RECT  42.696 30.204 42.714 30.209 ;
     RECT  43.956 27.941 43.974 30.209 ;
    LAYER M4 ;
     RECT  2.408 2.148 2.512 27.552 ;
     RECT  2.512 2.418 2.6 27.552 ;
     RECT  2.6 2.418 2.704 27.822 ;
     RECT  5.108 2.148 5.212 27.552 ;
     RECT  5.212 2.418 5.3 27.552 ;
     RECT  5.3 2.418 5.404 27.822 ;
     RECT  7.808 2.148 7.912 27.552 ;
     RECT  7.912 2.418 8 27.552 ;
     RECT  8 2.418 8.104 27.822 ;
     RECT  8.104 2.688 9.107 3.864 ;
     RECT  9.107 3.408 10.508 3.432 ;
     RECT  9.709 6.192 10.508 6.216 ;
     RECT  9.745 8.448 10.508 8.472 ;
     RECT  10.508 2.148 10.612 27.552 ;
     RECT  10.612 2.418 10.7 27.552 ;
     RECT  10.7 2.418 10.804 27.822 ;
     RECT  10.804 3.408 11.869 3.432 ;
     RECT  10.804 4.512 12.049 5.064 ;
     RECT  10.804 6.096 12.049 6.12 ;
     RECT  12.049 4.512 12.089 6.12 ;
     RECT  12.373 7.2 12.409 7.224 ;
     RECT  10.804 8.448 12.517 8.472 ;
     RECT  11.869 2.784 12.565 3.432 ;
     RECT  12.517 8.448 13.201 9.384 ;
     RECT  12.565 2.688 13.208 3.432 ;
     RECT  12.089 5.136 13.208 6.12 ;
     RECT  12.409 7.2 13.208 7.368 ;
     RECT  13.201 8.448 13.208 9.576 ;
     RECT  13.208 2.148 13.312 27.552 ;
     RECT  13.312 2.418 13.4 27.552 ;
     RECT  13.4 2.418 13.504 27.822 ;
     RECT  13.504 2.64 13.565 6.12 ;
     RECT  13.504 18.576 13.673 18.792 ;
     RECT  13.504 7.2 14.291 10.008 ;
     RECT  14.291 9.744 14.429 10.008 ;
     RECT  14.291 7.2 14.435 7.464 ;
     RECT  14.429 9.984 14.435 10.008 ;
     RECT  13.565 2.64 14.569 5.592 ;
     RECT  14.291 8.688 14.645 8.712 ;
     RECT  13.504 23.952 15.073 24.552 ;
     RECT  13.504 11.136 15.253 11.16 ;
     RECT  13.504 12.336 15.253 12.36 ;
     RECT  15.145 18.768 15.356 18.792 ;
     RECT  15.253 11.136 15.541 12.36 ;
     RECT  15.541 11.136 15.685 12.504 ;
     RECT  14.533 27.072 15.793 27.096 ;
     RECT  15.793 27.072 15.865 27.192 ;
     RECT  14.569 2.64 15.908 6.264 ;
     RECT  14.435 7.248 15.908 7.464 ;
     RECT  15.685 11.136 15.908 12.888 ;
     RECT  15.865 15.216 15.908 15.24 ;
     RECT  15.356 18.576 15.908 18.792 ;
     RECT  15.073 23.952 15.908 24.936 ;
     RECT  15.865 27.072 15.908 27.96 ;
     RECT  15.908 2.148 16.012 27.96 ;
     RECT  16.012 2.418 16.204 27.96 ;
     RECT  16.204 14.208 16.355 14.232 ;
     RECT  16.204 15.216 16.355 15.24 ;
     RECT  16.204 18.72 16.355 18.744 ;
     RECT  16.204 2.88 16.589 3.336 ;
     RECT  16.541 30.096 16.625 30.12 ;
     RECT  16.204 23.904 16.69 27.96 ;
     RECT  16.589 2.88 16.697 3.288 ;
     RECT  16.204 20.496 16.849 20.76 ;
     RECT  16.69 23.904 17.065 28.008 ;
     RECT  17.065 23.952 17.075 28.008 ;
     RECT  16.204 4.416 17.093 4.536 ;
     RECT  16.204 6.384 17.093 6.408 ;
     RECT  16.204 9.072 17.197 9.288 ;
     RECT  16.204 10.368 17.197 12.888 ;
     RECT  17.075 23.952 17.201 25.704 ;
     RECT  17.18 7.92 17.221 7.944 ;
     RECT  17.197 9.072 17.221 13.128 ;
     RECT  17.221 7.92 17.237 13.128 ;
     RECT  17.201 23.952 17.237 25.608 ;
     RECT  17.075 26.784 17.237 28.008 ;
     RECT  17.237 7.92 17.267 11.976 ;
     RECT  17.237 23.952 17.309 24.504 ;
     RECT  17.237 27.168 17.405 28.008 ;
     RECT  16.697 3.264 17.489 3.288 ;
     RECT  16.849 20.736 17.507 20.76 ;
     RECT  17.237 13.104 17.953 13.128 ;
     RECT  16.204 16.368 17.953 16.392 ;
     RECT  17.953 19.392 17.989 19.416 ;
     RECT  17.953 13.104 18.061 13.608 ;
     RECT  17.917 7.2 18.205 7.416 ;
     RECT  17.405 27.168 18.229 28.536 ;
     RECT  17.093 4.512 18.277 4.536 ;
     RECT  17.989 18.576 18.277 19.416 ;
     RECT  17.237 25.584 18.325 25.608 ;
     RECT  18.325 25.584 18.373 25.656 ;
     RECT  18.205 6.96 18.385 7.416 ;
     RECT  17.309 24.432 18.421 24.504 ;
     RECT  18.373 25.584 18.421 26.136 ;
     RECT  17.989 15.264 18.457 15.288 ;
     RECT  17.953 16.368 18.457 16.824 ;
     RECT  18.229 27.168 18.515 28.632 ;
     RECT  18.277 3.6 18.565 4.536 ;
     RECT  18.565 3.408 18.608 4.536 ;
     RECT  18.385 6.912 18.608 7.416 ;
     RECT  17.267 8.496 18.608 11.976 ;
     RECT  18.061 13.104 18.608 14.232 ;
     RECT  18.457 15.264 18.608 16.824 ;
     RECT  18.277 18.24 18.608 19.416 ;
     RECT  18.428 20.448 18.608 20.472 ;
     RECT  18.421 24.432 18.608 26.136 ;
     RECT  18.515 27.168 18.608 28.488 ;
     RECT  18.608 2.148 18.712 28.488 ;
     RECT  18.712 2.418 18.904 28.488 ;
     RECT  18.904 25.2 19.043 27.336 ;
     RECT  18.421 30.048 19.043 30.072 ;
     RECT  18.904 14.928 19.045 16.824 ;
     RECT  18.904 19.968 19.081 21.816 ;
     RECT  18.904 28.464 19.109 28.488 ;
     RECT  18.904 8.496 19.181 11.448 ;
     RECT  18.904 12.816 19.181 13.704 ;
     RECT  19.181 13.584 19.217 13.704 ;
     RECT  18.904 23.856 19.333 23.928 ;
     RECT  19.081 19.968 19.369 20.52 ;
     RECT  18.904 6.576 19.433 7.464 ;
     RECT  19.433 7.44 19.469 7.464 ;
     RECT  19.333 23.856 19.475 23.88 ;
     RECT  19.181 8.496 19.505 10.344 ;
     RECT  19.081 21.792 19.505 21.816 ;
     RECT  19.043 25.296 19.505 27.336 ;
     RECT  19.505 25.296 19.613 26.808 ;
     RECT  19.181 11.424 19.685 11.448 ;
     RECT  19.505 8.496 19.721 8.52 ;
     RECT  19.505 9.744 19.757 10.344 ;
     RECT  19.045 14.928 19.829 15.288 ;
     RECT  19.613 25.296 19.865 26.664 ;
     RECT  19.045 16.512 19.909 16.824 ;
     RECT  19.909 16.512 19.955 16.968 ;
     RECT  18.904 18.24 19.955 18.984 ;
     RECT  19.865 25.296 20.005 26.472 ;
     RECT  19.955 16.608 20.081 16.968 ;
     RECT  20.005 25.104 20.089 26.472 ;
     RECT  19.217 13.68 20.113 13.704 ;
     RECT  19.829 15.264 20.153 15.288 ;
     RECT  20.245 22.176 20.252 22.2 ;
     RECT  20.252 22.176 20.339 22.632 ;
     RECT  20.339 22.176 20.581 22.2 ;
     RECT  20.437 11.952 20.689 11.976 ;
     RECT  20.581 22.128 20.725 22.2 ;
     RECT  20.689 11.088 20.773 11.976 ;
     RECT  20.113 13.68 20.773 13.848 ;
     RECT  20.869 7.92 21.013 7.944 ;
     RECT  20.081 16.608 21.121 16.68 ;
     RECT  19.757 9.744 21.157 9.768 ;
     RECT  20.773 11.088 21.157 13.848 ;
     RECT  18.904 2.496 21.308 4.488 ;
     RECT  18.904 5.472 21.308 5.496 ;
     RECT  21.013 7.44 21.308 7.944 ;
     RECT  21.157 9.648 21.308 9.768 ;
     RECT  21.157 10.752 21.308 13.848 ;
     RECT  21.121 16.56 21.308 16.68 ;
     RECT  19.955 18.96 21.308 18.984 ;
     RECT  19.369 20.16 21.308 20.52 ;
     RECT  20.725 21.792 21.308 22.2 ;
     RECT  20.089 25.68 21.308 26.472 ;
     RECT  21.308 2.148 21.412 27.552 ;
     RECT  21.412 2.256 21.5 27.552 ;
     RECT  21.5 2.256 21.604 27.822 ;
     RECT  21.604 18.672 21.701 18.984 ;
     RECT  21.604 2.256 21.845 5.496 ;
     RECT  21.845 2.256 21.971 5.208 ;
     RECT  21.604 16.56 22.097 16.632 ;
     RECT  21.604 20.88 22.097 22.104 ;
     RECT  21.971 2.496 22.133 5.208 ;
     RECT  21.604 7.536 22.277 7.56 ;
     RECT  22.097 20.88 22.277 21 ;
     RECT  21.481 0.048 22.385 0.072 ;
     RECT  21.701 18.672 22.493 18.792 ;
     RECT  21.604 11.424 22.529 12.552 ;
     RECT  22.529 11.424 22.547 12.216 ;
     RECT  21.604 13.632 22.565 14.952 ;
     RECT  22.097 22.08 22.597 22.104 ;
     RECT  22.597 22.08 22.633 23.016 ;
     RECT  21.604 8.688 22.637 9.528 ;
     RECT  22.633 22.08 22.643 23.4 ;
     RECT  22.277 20.976 22.889 21 ;
     RECT  22.957 18.816 23.041 18.84 ;
     RECT  22.637 9.216 23.173 9.528 ;
     RECT  22.547 11.424 23.173 11.928 ;
     RECT  22.565 13.92 23.173 14.952 ;
     RECT  22.097 16.56 23.209 16.584 ;
     RECT  23.209 16.56 23.245 16.872 ;
     RECT  22.133 2.784 23.605 5.208 ;
     RECT  22.643 22.224 23.713 23.4 ;
     RECT  23.713 22.032 23.749 23.4 ;
     RECT  23.605 2.256 23.797 5.208 ;
     RECT  23.281 7.968 23.893 7.992 ;
     RECT  23.173 9.216 23.893 11.928 ;
     RECT  23.797 2.256 24.008 5.544 ;
     RECT  23.893 7.968 24.008 11.976 ;
     RECT  23.173 13.92 24.008 15.24 ;
     RECT  23.245 16.224 24.008 16.872 ;
     RECT  24.001 18.768 24.008 18.792 ;
     RECT  23.749 21.936 24.008 23.4 ;
     RECT  23.857 25.2 24.008 25.224 ;
     RECT  24.008 2.148 24.112 27.552 ;
     RECT  24.112 2.418 24.2 27.552 ;
     RECT  24.2 2.418 24.304 27.822 ;
     RECT  24.304 17.952 24.401 19.032 ;
     RECT  24.304 24.48 24.419 25.56 ;
     RECT  24.419 25.104 24.467 25.56 ;
     RECT  24.304 15.216 24.581 15.672 ;
     RECT  24.428 30.144 24.709 30.168 ;
     RECT  24.304 3.312 24.833 7.992 ;
     RECT  24.581 15.264 24.851 15.672 ;
     RECT  24.304 26.64 24.851 27.72 ;
     RECT  24.304 21.936 24.869 23.4 ;
     RECT  24.851 26.64 24.869 27.384 ;
     RECT  24.869 27.36 24.977 27.384 ;
     RECT  24.833 7.008 25.085 7.992 ;
     RECT  24.304 11.952 25.165 14.184 ;
     RECT  24.869 21.936 25.532 22.824 ;
     RECT  24.467 25.104 25.573 25.224 ;
     RECT  25.513 26.208 25.573 26.232 ;
     RECT  25.573 25.104 25.585 26.232 ;
     RECT  25.165 13.296 25.661 14.184 ;
     RECT  24.851 15.264 25.697 15.288 ;
     RECT  25.621 20.256 25.729 20.28 ;
     RECT  25.532 21.264 25.729 22.824 ;
     RECT  24.833 3.312 25.733 6.024 ;
     RECT  25.585 25.008 25.909 26.232 ;
     RECT  25.909 25.008 25.964 26.424 ;
     RECT  25.369 16.848 26.017 16.872 ;
     RECT  24.401 18 26.053 19.032 ;
     RECT  25.729 20.256 26.053 22.824 ;
     RECT  25.964 25.008 26.053 26.664 ;
     RECT  25.733 3.312 26.149 5.88 ;
     RECT  24.709 29.664 26.195 30.168 ;
     RECT  26.195 29.664 26.201 29.688 ;
     RECT  26.053 0.096 26.233 0.12 ;
     RECT  26.233 0.096 26.3 0.6 ;
     RECT  26.3 0.096 26.387 1.128 ;
     RECT  26.017 16.656 26.413 16.872 ;
     RECT  26.053 18 26.413 22.824 ;
     RECT  24.304 8.976 26.581 9 ;
     RECT  25.165 11.952 26.665 11.976 ;
     RECT  26.581 8.976 26.701 9.096 ;
     RECT  26.521 1.728 26.708 1.752 ;
     RECT  26.149 2.88 26.708 5.88 ;
     RECT  25.085 7.056 26.708 7.992 ;
     RECT  26.701 8.976 26.708 9.816 ;
     RECT  26.665 11.952 26.708 12.552 ;
     RECT  25.661 14.16 26.708 14.184 ;
     RECT  26.413 16.656 26.708 22.824 ;
     RECT  26.053 24.528 26.708 26.664 ;
     RECT  26.387 0.096 26.771 0.552 ;
     RECT  26.708 1.728 26.9 27.552 ;
     RECT  26.9 1.728 27.004 27.822 ;
     RECT  27.004 6.912 27.155 9.816 ;
     RECT  27.004 1.728 27.173 5.88 ;
     RECT  27.155 8.448 27.173 9.816 ;
     RECT  27.004 11.952 27.173 12.552 ;
     RECT  27.004 25.44 27.299 26.328 ;
     RECT  27.155 6.912 27.317 7.464 ;
     RECT  27.004 14.016 27.433 18.168 ;
     RECT  27.433 15.696 27.641 18.168 ;
     RECT  27.004 20.928 27.641 23.304 ;
     RECT  27.173 1.728 27.713 5.784 ;
     RECT  26.771 0.096 27.773 0.12 ;
     RECT  27.173 8.448 27.785 9.096 ;
     RECT  27.773 0.096 27.857 0.552 ;
     RECT  27.641 21.12 28.037 23.304 ;
     RECT  27.713 1.728 28.105 4.008 ;
     RECT  27.641 16.272 28.253 18.168 ;
     RECT  28.105 1.104 28.307 4.008 ;
     RECT  28.253 17.088 28.361 18.168 ;
     RECT  28.361 17.088 28.397 17.688 ;
     RECT  27.317 7.44 28.501 7.464 ;
     RECT  27.857 0.096 28.613 0.12 ;
     RECT  28.609 10.608 28.645 10.632 ;
     RECT  27.785 9.072 28.681 9.096 ;
     RECT  28.645 10.608 28.717 10.92 ;
     RECT  28.037 21.12 28.753 22.488 ;
     RECT  28.501 7.44 28.825 7.752 ;
     RECT  27.173 12.528 28.861 12.552 ;
     RECT  27.433 14.016 28.861 14.184 ;
     RECT  27.299 25.44 29.113 25.464 ;
     RECT  28.861 12.528 29.269 14.184 ;
     RECT  28.969 15.216 29.269 15.24 ;
     RECT  28.307 1.728 29.333 4.008 ;
     RECT  29.333 1.824 29.408 4.008 ;
     RECT  27.713 5.376 29.408 5.784 ;
     RECT  28.825 6.864 29.408 7.752 ;
     RECT  28.681 9.072 29.408 9.144 ;
     RECT  28.717 10.608 29.408 10.968 ;
     RECT  29.269 12.528 29.408 15.24 ;
     RECT  28.397 17.088 29.408 17.64 ;
     RECT  28.573 18.72 29.408 18.744 ;
     RECT  28.753 20.592 29.408 22.488 ;
     RECT  29.113 24.72 29.408 25.464 ;
     RECT  29.408 1.824 29.6 27.552 ;
     RECT  29.6 1.824 29.704 27.822 ;
     RECT  29.704 1.824 29.801 3.912 ;
     RECT  29.704 5.76 29.801 5.88 ;
     RECT  29.704 15.216 30.089 15.24 ;
     RECT  29.704 20.592 30.089 22.488 ;
     RECT  29.704 17.088 30.197 17.496 ;
     RECT  29.801 1.872 30.233 3.912 ;
     RECT  30.233 1.968 30.269 3.912 ;
     RECT  29.704 7.488 30.275 7.848 ;
     RECT  30.269 2.544 30.449 3.912 ;
     RECT  29.704 10.608 30.668 10.632 ;
     RECT  30.668 10.608 30.755 11.544 ;
     RECT  30.197 17.472 30.769 17.496 ;
     RECT  29.704 18.72 30.769 18.744 ;
     RECT  30.449 3.168 30.881 3.912 ;
     RECT  30.769 17.472 30.953 18.744 ;
     RECT  30.881 3.408 30.989 3.912 ;
     RECT  30.089 21.12 30.989 22.488 ;
     RECT  30.275 7.488 31.097 7.8 ;
     RECT  29.704 24.72 31.097 24.744 ;
     RECT  31.097 7.536 31.133 7.8 ;
     RECT  29.704 12.528 31.453 14.184 ;
     RECT  30.769 20.112 31.916 20.136 ;
     RECT  31.621 9.36 31.957 9.384 ;
     RECT  31.916 20.112 31.957 20.664 ;
     RECT  30.989 21.792 31.957 22.488 ;
     RECT  30.953 18.72 31.993 18.744 ;
     RECT  31.993 18.72 32.029 18.84 ;
     RECT  32.029 18.624 32.065 18.84 ;
     RECT  30.989 3.888 32.108 3.912 ;
     RECT  29.801 5.856 32.108 5.88 ;
     RECT  31.133 7.536 32.108 7.56 ;
     RECT  31.957 9.264 32.108 9.384 ;
     RECT  30.755 10.608 32.108 10.92 ;
     RECT  31.453 12.528 32.108 14.808 ;
     RECT  31.957 16.368 32.108 16.392 ;
     RECT  30.953 17.472 32.108 17.496 ;
     RECT  32.065 18.624 32.108 18.984 ;
     RECT  31.957 20.112 32.108 22.488 ;
     RECT  32.108 2.148 32.212 27.552 ;
     RECT  32.212 2.418 32.3 27.552 ;
     RECT  32.3 2.418 32.404 27.822 ;
     RECT  32.404 20.304 32.465 22.488 ;
     RECT  32.404 9.888 32.717 10.92 ;
     RECT  32.404 13.536 33.1 16.584 ;
     RECT  32.404 12.528 33.293 12.552 ;
     RECT  32.404 18.912 33.293 19.272 ;
     RECT  33.1 13.68 33.541 16.584 ;
     RECT  32.404 17.664 33.541 17.688 ;
     RECT  32.465 20.304 33.653 21.672 ;
     RECT  32.717 9.888 33.829 10.776 ;
     RECT  33.293 18.912 34.001 18.936 ;
     RECT  33.829 9.84 34.045 10.776 ;
     RECT  34.001 18.816 34.333 18.936 ;
     RECT  33.653 20.304 34.333 20.328 ;
     RECT  32.404 3.888 34.585 3.912 ;
     RECT  34.045 9.744 34.765 10.776 ;
     RECT  34.693 11.76 34.765 11.784 ;
     RECT  34.585 3.888 34.808 4.152 ;
     RECT  34.765 9.744 34.808 11.784 ;
     RECT  33.541 13.68 34.808 17.688 ;
     RECT  34.333 18.816 34.808 20.328 ;
     RECT  34.808 2.148 34.912 27.552 ;
     RECT  34.912 2.418 35 27.552 ;
     RECT  35 2.418 35.104 27.822 ;
     RECT  35.104 6.816 35.315 8.76 ;
     RECT  35.104 15.552 35.381 16.392 ;
     RECT  35.315 6.96 35.453 8.76 ;
     RECT  35.104 17.568 35.507 17.688 ;
     RECT  35.507 17.616 35.597 17.688 ;
     RECT  35.104 10.704 35.603 11.448 ;
     RECT  35.603 10.8 35.785 11.448 ;
     RECT  35.453 6.96 35.849 8.712 ;
     RECT  35.849 6.96 35.993 6.984 ;
     RECT  35.785 10.896 36.065 11.448 ;
     RECT  35.849 8.016 36.173 8.712 ;
     RECT  35.104 2.832 36.241 4.152 ;
     RECT  35.104 5.184 36.241 5.736 ;
     RECT  36.241 2.832 36.277 5.736 ;
     RECT  35.104 19.824 36.385 20.088 ;
     RECT  35.381 15.84 36.469 16.392 ;
     RECT  36.385 19.824 36.469 20.808 ;
     RECT  36.469 15.84 36.515 16.536 ;
     RECT  35.104 13.584 36.745 14.472 ;
     RECT  36.469 19.824 36.925 21.384 ;
     RECT  36.515 16.368 36.997 16.536 ;
     RECT  35.597 17.616 36.997 17.64 ;
     RECT  36.745 13.584 37.033 14.808 ;
     RECT  36.781 18.816 37.033 18.84 ;
     RECT  37.033 13.584 37.141 14.856 ;
     RECT  36.889 12.336 37.177 12.36 ;
     RECT  36.997 16.368 37.177 17.64 ;
     RECT  37.033 18.768 37.177 18.84 ;
     RECT  37.177 12.288 37.285 12.36 ;
     RECT  36.925 19.824 37.285 21.528 ;
     RECT  36.757 26.112 37.285 26.136 ;
     RECT  36.173 8.544 37.333 8.712 ;
     RECT  37.285 25.68 37.333 26.136 ;
     RECT  37.333 25.584 37.381 26.136 ;
     RECT  36.716 30.144 37.381 30.168 ;
     RECT  36.277 2.496 37.508 5.736 ;
     RECT  37.333 8.256 37.508 8.712 ;
     RECT  36.065 10.896 37.508 10.92 ;
     RECT  37.285 12.288 37.508 12.552 ;
     RECT  37.141 13.584 37.508 15.336 ;
     RECT  37.177 16.368 37.508 18.84 ;
     RECT  37.285 19.824 37.508 22.2 ;
     RECT  37.381 25.2 37.508 26.136 ;
     RECT  37.381 29.664 37.577 30.168 ;
     RECT  37.508 2.148 37.612 27.552 ;
     RECT  37.612 2.418 37.7 27.552 ;
     RECT  37.7 2.418 37.804 27.822 ;
     RECT  37.804 10.272 37.955 17.16 ;
     RECT  37.577 30 38.003 30.168 ;
     RECT  37.955 10.896 38.081 17.16 ;
     RECT  38.003 30.048 38.099 30.168 ;
     RECT  37.804 2.496 38.189 5.208 ;
     RECT  38.099 30.096 38.195 30.168 ;
     RECT  37.804 18.432 38.225 22.2 ;
     RECT  38.195 30.096 38.291 30.12 ;
     RECT  38.189 2.64 38.369 5.208 ;
     RECT  37.804 24.528 38.369 26.424 ;
     RECT  38.225 18.432 38.38 20.52 ;
     RECT  38.081 11.808 38.405 14.856 ;
     RECT  37.804 7.968 38.441 8.568 ;
     RECT  38.38 18.432 38.483 19.32 ;
     RECT  37.804 6.24 38.513 6.84 ;
     RECT  38.369 24.528 38.521 24.552 ;
     RECT  38.405 11.952 38.549 14.856 ;
     RECT  38.369 25.68 38.621 26.424 ;
     RECT  38.483 18.432 38.765 18.84 ;
     RECT  38.621 25.68 38.771 26.232 ;
     RECT  38.369 4.128 38.797 5.208 ;
     RECT  38.513 6.24 38.797 6.264 ;
     RECT  38.441 8.16 38.873 8.568 ;
     RECT  38.869 9.6 39.013 9.624 ;
     RECT  38.549 11.952 39.053 14.664 ;
     RECT  38.771 25.68 39.161 25.896 ;
     RECT  38.369 2.64 39.197 2.664 ;
     RECT  38.38 20.496 39.253 20.52 ;
     RECT  38.225 21.504 39.253 22.2 ;
     RECT  39.253 20.496 39.553 22.2 ;
     RECT  39.445 10.896 39.625 10.92 ;
     RECT  39.013 9.456 39.692 9.624 ;
     RECT  39.625 10.896 39.692 11.208 ;
     RECT  38.797 4.128 39.733 6.264 ;
     RECT  38.765 18.432 39.761 18.456 ;
     RECT  39.053 12.336 39.769 14.664 ;
     RECT  38.873 8.16 39.805 8.184 ;
     RECT  39.553 20.496 39.877 22.776 ;
     RECT  39.877 19.968 39.925 22.776 ;
     RECT  39.661 2.784 40.208 2.808 ;
     RECT  39.733 3.84 40.208 6.264 ;
     RECT  39.805 7.632 40.208 8.184 ;
     RECT  39.692 9.456 40.208 11.208 ;
     RECT  39.769 12.336 40.208 14.76 ;
     RECT  38.081 15.984 40.208 17.16 ;
     RECT  39.761 18.288 40.208 18.456 ;
     RECT  39.925 19.68 40.208 22.776 ;
     RECT  39.161 25.68 40.208 25.704 ;
     RECT  40.208 2.148 40.312 27.552 ;
     RECT  40.312 2.418 40.4 27.552 ;
     RECT  40.4 2.418 40.504 27.822 ;
     RECT  40.504 16.368 40.601 16.92 ;
     RECT  40.504 10.368 40.673 11.16 ;
     RECT  40.604 30.144 40.69 30.168 ;
     RECT  40.69 30.096 40.805 30.168 ;
     RECT  40.504 2.418 41.213 6.648 ;
     RECT  41.213 3.264 41.285 6.648 ;
     RECT  41.317 2.256 41.411 2.28 ;
     RECT  40.504 18.144 41.497 18.168 ;
     RECT  40.504 21.792 41.497 22.872 ;
     RECT  40.504 25.056 41.509 27.24 ;
     RECT  41.497 18.144 41.533 18.792 ;
     RECT  40.504 20.16 41.533 20.184 ;
     RECT  41.533 18.144 41.603 20.184 ;
     RECT  41.603 18.768 41.609 20.184 ;
     RECT  40.504 13.68 41.641 14.76 ;
     RECT  40.601 16.368 41.641 16.872 ;
     RECT  41.609 18.816 41.653 20.184 ;
     RECT  41.641 13.68 41.681 16.872 ;
     RECT  41.285 4.368 41.713 6.648 ;
     RECT  40.504 7.632 41.713 8.52 ;
     RECT  41.713 4.368 41.753 8.52 ;
     RECT  41.497 21.792 41.821 23.352 ;
     RECT  41.821 21.36 41.861 23.352 ;
     RECT  41.861 22.752 41.933 23.352 ;
     RECT  41.653 18.816 42.085 20.28 ;
     RECT  41.861 21.36 42.085 21.384 ;
     RECT  40.805 29.664 42.179 30.168 ;
     RECT  41.285 3.264 42.181 3.336 ;
     RECT  40.673 10.56 42.181 11.16 ;
     RECT  42.181 9.648 42.325 11.16 ;
     RECT  41.681 13.68 42.325 14.472 ;
     RECT  41.753 7.44 42.332 8.52 ;
     RECT  42.325 9.648 42.332 11.688 ;
     RECT  42.433 0.048 42.572 0.072 ;
     RECT  42.572 0.048 42.581 0.168 ;
     RECT  42.581 0.144 42.605 0.168 ;
     RECT  42.605 0.144 42.659 0.264 ;
     RECT  42.659 0.24 42.689 0.264 ;
     RECT  42.179 30.144 42.725 30.168 ;
     RECT  42.181 2.64 42.757 3.336 ;
     RECT  41.681 15.6 42.757 16.872 ;
     RECT  42.757 2.304 42.793 3.336 ;
     RECT  41.753 4.368 42.793 6.408 ;
     RECT  42.793 2.304 42.908 6.408 ;
     RECT  42.332 7.44 42.908 11.688 ;
     RECT  42.325 12.72 42.908 14.472 ;
     RECT  42.757 15.456 42.908 16.872 ;
     RECT  42.085 18.816 42.908 21.384 ;
     RECT  41.933 22.848 42.908 23.352 ;
     RECT  41.509 25.056 42.908 27.912 ;
     RECT  42.908 2.148 43.012 27.912 ;
     RECT  43.012 2.304 43.204 27.912 ;
     RECT  43.204 2.304 43.265 4.68 ;
     RECT  43.204 7.44 43.373 11.16 ;
     RECT  43.204 6.288 43.481 6.408 ;
     RECT  43.204 13.296 43.617 23.352 ;
     RECT  43.617 13.296 43.733 17.112 ;
     RECT  43.617 18.72 43.733 23.352 ;
     RECT  43.204 24.528 43.777 27.912 ;
     RECT  43.777 25.68 43.805 27.912 ;
     RECT  43.733 13.584 43.841 17.112 ;
     RECT  43.733 18.72 43.949 21.816 ;
     RECT  43.373 9.072 44.021 11.16 ;
     RECT  43.841 13.68 44.021 17.112 ;
     RECT  44.021 9.36 44.044 11.16 ;
     RECT  43.373 7.44 44.057 7.464 ;
     RECT  43.805 25.68 44.057 27.624 ;
     RECT  43.733 22.992 44.129 23.352 ;
     RECT  43.481 6.384 44.197 6.408 ;
     RECT  44.057 25.68 44.425 26.232 ;
     RECT  44.129 23.28 44.453 23.352 ;
     RECT  44.425 26.208 44.483 26.232 ;
     RECT  43.777 24.528 44.489 24.552 ;
     RECT  43.265 2.304 44.597 3.336 ;
     RECT  44.197 6.384 44.629 6.552 ;
     RECT  44.629 12.384 44.737 12.408 ;
     RECT  44.629 6 45.013 6.552 ;
     RECT  44.044 10.464 45.025 11.16 ;
     RECT  44.737 12.384 45.025 12.552 ;
     RECT  43.265 4.56 45.169 4.68 ;
     RECT  45.013 5.856 45.169 6.552 ;
     RECT  44.989 8.016 45.205 8.04 ;
     RECT  45.025 10.464 45.241 12.552 ;
     RECT  45.313 1.104 45.385 1.128 ;
     RECT  44.629 2.256 45.385 2.28 ;
     RECT  44.597 3.312 45.452 3.336 ;
     RECT  45.169 4.56 45.452 6.552 ;
     RECT  44.021 15.024 45.529 17.112 ;
     RECT  43.949 18.72 45.529 19.944 ;
     RECT  45.385 1.104 45.608 2.28 ;
     RECT  45.452 3.312 45.608 6.552 ;
     RECT  45.205 8.016 45.608 8.088 ;
     RECT  44.044 9.36 45.608 9.384 ;
     RECT  45.241 10.368 45.608 12.552 ;
     RECT  44.021 13.68 45.608 13.944 ;
     RECT  45.529 15.024 45.608 19.944 ;
     RECT  43.949 20.976 45.608 21.816 ;
     RECT  44.453 23.28 45.608 23.304 ;
     RECT  44.057 27.6 45.608 27.624 ;
     RECT  45.608 1.104 45.683 27.624 ;
     RECT  45.133 0.096 45.745 0.12 ;
     RECT  45.683 1.68 45.779 27.624 ;
     RECT  45.779 1.728 45.8 27.624 ;
     RECT  45.8 1.728 45.904 27.822 ;
     RECT  45.904 1.728 46.001 9.096 ;
     RECT  45.904 23.28 46.019 24.648 ;
     RECT  45.904 10.224 46.037 12.504 ;
     RECT  45.745 0.096 46.109 0.6 ;
     RECT  46.001 1.728 46.217 9 ;
     RECT  46.217 1.728 46.355 8.52 ;
     RECT  46.019 23.28 46.433 24.456 ;
     RECT  46.037 10.224 46.505 10.728 ;
     RECT  45.904 13.68 46.505 19.992 ;
     RECT  46.355 3.936 46.588 8.52 ;
     RECT  46.505 18.96 46.739 19.992 ;
     RECT  46.505 13.68 46.757 17.928 ;
     RECT  46.757 13.68 46.865 16.632 ;
     RECT  46.739 18.96 46.865 19.848 ;
     RECT  46.588 4.224 46.901 8.52 ;
     RECT  46.433 23.856 46.937 24.456 ;
     RECT  46.109 0.096 47.045 0.552 ;
     RECT  46.865 13.68 47.189 16.536 ;
     RECT  47.189 16.032 47.297 16.536 ;
     RECT  46.355 1.728 47.333 2.952 ;
     RECT  45.904 21.504 47.365 22.152 ;
     RECT  46.505 10.224 47.473 10.248 ;
     RECT  46.901 6.912 47.545 8.52 ;
     RECT  46.037 12.48 47.653 12.504 ;
     RECT  46.901 4.224 47.941 5.88 ;
     RECT  47.545 6.912 47.941 9.048 ;
     RECT  47.473 10.08 48.013 10.248 ;
     RECT  46.865 19.2 48.013 19.848 ;
     RECT  47.941 4.224 48.149 9.048 ;
     RECT  48.013 10.08 48.149 11.448 ;
     RECT  46.757 17.904 48.193 17.928 ;
     RECT  48.013 19.2 48.193 20.424 ;
     RECT  47.045 0.096 48.221 0.264 ;
     RECT  48.221 0.096 48.305 0.312 ;
     RECT  47.333 1.728 48.308 2.904 ;
     RECT  48.149 4.224 48.308 11.448 ;
     RECT  47.653 12.48 48.308 12.6 ;
     RECT  47.189 13.68 48.308 15.048 ;
     RECT  47.297 16.128 48.308 16.536 ;
     RECT  48.193 17.904 48.308 20.424 ;
     RECT  47.365 21.504 48.308 22.776 ;
     RECT  46.937 23.856 48.308 23.88 ;
     RECT  47.317 24.864 48.308 24.888 ;
     RECT  48.308 1.728 48.485 27.552 ;
     RECT  48.485 1.776 48.5 27.552 ;
     RECT  48.5 1.776 48.604 27.822 ;
     RECT  48.604 3.984 48.665 9.72 ;
     RECT  48.665 3.984 48.755 7.944 ;
     RECT  48.604 2.88 48.845 2.904 ;
     RECT  48.305 0.096 48.989 0.264 ;
     RECT  48.604 22.752 48.989 22.824 ;
     RECT  48.755 6.816 48.995 7.944 ;
     RECT  48.604 14.928 49.025 16.008 ;
     RECT  48.604 10.896 49.097 11.448 ;
     RECT  48.604 17.088 49.133 17.112 ;
     RECT  48.989 22.8 49.133 22.824 ;
     RECT  48.604 1.776 49.169 1.8 ;
     RECT  48.989 0.144 49.205 0.264 ;
     RECT  49.205 0.144 49.313 0.216 ;
     RECT  49.097 10.896 49.313 11.4 ;
     RECT  48.755 3.984 49.529 5.64 ;
     RECT  48.665 8.976 49.565 9.72 ;
     RECT  48.604 12.48 49.565 12.552 ;
     RECT  49.565 9.072 49.601 9.72 ;
     RECT  48.995 6.816 49.637 7.704 ;
     RECT  49.025 15.024 49.745 16.008 ;
     RECT  49.565 12.528 49.817 12.552 ;
     RECT  49.529 5.04 49.82 5.64 ;
     RECT  49.637 6.816 49.82 6.936 ;
     RECT  49.82 5.04 49.907 6.936 ;
     RECT  49.313 11.184 49.925 11.4 ;
     RECT  48.604 23.856 49.964 23.88 ;
     RECT  49.313 0.192 50.213 0.216 ;
     RECT  50.173 22.8 50.281 22.824 ;
     RECT  50.281 22.8 50.492 22.872 ;
     RECT  49.964 23.856 50.492 24.6 ;
     RECT  49.601 9.072 50.725 9.096 ;
     RECT  49.907 6.816 50.893 6.936 ;
     RECT  49.925 11.376 50.893 11.4 ;
     RECT  49.529 3.984 51.008 4.008 ;
     RECT  49.907 5.184 51.008 5.64 ;
     RECT  50.893 6.816 51.008 7.368 ;
     RECT  50.725 8.496 51.008 9.096 ;
     RECT  50.893 11.232 51.008 11.4 ;
     RECT  50.893 12.528 51.008 12.552 ;
     RECT  48.604 13.68 51.008 13.944 ;
     RECT  49.745 15.024 51.008 15.336 ;
     RECT  48.604 18.816 51.008 18.84 ;
     RECT  48.604 20.4 51.008 21.096 ;
     RECT  50.492 22.8 51.008 24.6 ;
     RECT  51.008 2.148 51.112 27.552 ;
     RECT  51.112 2.418 51.2 27.552 ;
     RECT  51.2 2.418 51.304 27.822 ;
     RECT  51.304 4.896 51.443 9.336 ;
     RECT  51.304 22.8 51.443 22.824 ;
     RECT  51.304 23.904 51.443 24.648 ;
     RECT  51.304 16.368 51.445 21.72 ;
     RECT  51.445 18.816 51.509 21.72 ;
     RECT  51.304 11.232 51.581 15.336 ;
     RECT  51.443 5.568 51.653 9.336 ;
     RECT  51.581 11.664 51.653 15.336 ;
     RECT  51.653 11.664 51.676 15.144 ;
     RECT  51.509 18.816 51.761 20.52 ;
     RECT  51.653 6 51.779 9.336 ;
     RECT  51.445 16.368 51.875 17.16 ;
     RECT  51.779 6 52.019 8.136 ;
     RECT  51.779 9.216 52.019 9.336 ;
     RECT  51.676 11.664 52.193 14.376 ;
     RECT  51.761 19.776 52.307 20.52 ;
     RECT  52.307 19.776 52.337 20.184 ;
     RECT  51.875 16.992 52.549 17.16 ;
     RECT  52.549 16.992 52.585 17.256 ;
     RECT  52.585 16.992 52.589 17.448 ;
     RECT  51.443 23.904 52.661 23.928 ;
     RECT  51.509 21.696 52.837 21.72 ;
     RECT  52.589 17.04 53.017 17.448 ;
     RECT  52.337 19.776 53.161 19.8 ;
     RECT  52.019 6 53.197 7.992 ;
     RECT  52.193 13.68 53.269 14.376 ;
     RECT  52.837 21.696 53.341 22.2 ;
     RECT  53.197 6 53.708 8.232 ;
     RECT  52.019 9.216 53.708 9.24 ;
     RECT  53.017 10.224 53.708 10.248 ;
     RECT  52.193 11.664 53.708 12.504 ;
     RECT  53.269 13.68 53.708 14.472 ;
     RECT  53.017 17.04 53.708 17.976 ;
     RECT  53.161 19.248 53.708 19.8 ;
     RECT  53.341 21.696 53.708 22.776 ;
     RECT  53.708 2.148 53.812 27.552 ;
     RECT  53.812 2.418 53.9 27.552 ;
     RECT  53.9 2.418 54.004 27.822 ;
     RECT  54.004 7.68 54.173 8.232 ;
     RECT  54.004 18.768 54.677 19.992 ;
     RECT  54.677 18.768 54.707 19.464 ;
     RECT  54.004 13.008 54.929 17.448 ;
     RECT  54.707 18.768 54.929 18.792 ;
     RECT  54.929 15.696 54.947 17.448 ;
     RECT  54.947 15.696 55.001 17.16 ;
     RECT  55.001 16.512 55.109 16.68 ;
     RECT  54.173 8.16 55.244 8.232 ;
     RECT  55.244 8.16 55.249 8.664 ;
     RECT  55.177 9.648 55.285 9.672 ;
     RECT  54.004 10.848 55.285 11.976 ;
     RECT  55.109 16.656 55.325 16.68 ;
     RECT  55.249 7.968 55.331 8.664 ;
     RECT  55.285 9.648 55.331 11.976 ;
     RECT  55.331 7.968 55.333 7.992 ;
     RECT  55.331 10.272 56.408 11.976 ;
     RECT  54.929 13.008 56.408 14.52 ;
     RECT  56.408 2.148 56.512 27.552 ;
     RECT  56.512 2.418 56.6 27.552 ;
     RECT  56.6 2.418 56.704 27.822 ;
     RECT  56.704 13.68 57.053 15.288 ;
     RECT  57.053 15.264 57.881 15.288 ;
     RECT  57.053 13.68 59.108 13.944 ;
     RECT  59.108 2.148 59.212 27.552 ;
     RECT  59.212 2.418 59.3 27.552 ;
     RECT  59.3 2.418 59.404 27.822 ;
     RECT  59.404 13.68 61.808 13.944 ;
     RECT  61.808 2.148 61.912 27.552 ;
     RECT  61.912 2.418 62 27.552 ;
     RECT  62 2.418 62.104 27.822 ;
     RECT  62.104 13.68 63.277 14.088 ;
     RECT  63.277 13.68 64.692 13.704 ;
     RECT  63.277 13.704 64.716 13.776 ;
     RECT  63.277 13.776 64.692 13.8 ;
     RECT  63.277 13.8 64.716 13.872 ;
     RECT  63.277 13.872 64.692 13.896 ;
     RECT  63.277 13.896 64.716 13.968 ;
     RECT  63.277 13.968 64.692 13.992 ;
     RECT  63.277 13.992 64.716 14.064 ;
     RECT  63.277 14.064 64.692 14.088 ;
     RECT  63.277 14.088 64.716 14.16 ;
     RECT  63.277 14.16 64.692 14.184 ;
     RECT  63.277 14.184 64.716 14.256 ;
     RECT  63.277 14.256 64.692 14.28 ;
     RECT  63.277 14.28 64.716 14.352 ;
     RECT  63.277 14.352 64.692 14.376 ;
     RECT  63.277 14.376 64.716 14.448 ;
     RECT  63.277 14.448 64.692 14.472 ;
    LAYER M5 ;
     RECT  26.088 0.016 26.16 0.084 ;
     RECT  26.184 0.016 26.256 0.084 ;
     RECT  26.28 0.016 26.352 0.084 ;
     RECT  26.376 0.016 26.448 0.084 ;
     RECT  26.472 0.016 26.544 0.084 ;
     RECT  26.568 0.016 26.64 0.084 ;
     RECT  26.664 0.016 26.736 0.084 ;
     RECT  26.76 0.016 26.832 0.084 ;
     RECT  26.856 0.016 26.928 0.084 ;
     RECT  26.952 0.016 27.024 0.084 ;
     RECT  27.048 0.016 27.12 0.084 ;
     RECT  27.144 0.016 27.216 0.084 ;
     RECT  27.24 0.016 27.312 0.084 ;
     RECT  27.336 0.016 27.408 0.084 ;
     RECT  27.432 0.016 27.504 0.084 ;
     RECT  27.528 0.016 27.6 0.084 ;
     RECT  27.624 0.016 27.696 0.084 ;
     RECT  27.72 0.016 27.792 0.084 ;
     RECT  27.816 0.016 27.888 0.084 ;
     RECT  27.912 0.016 27.984 0.084 ;
     RECT  28.008 0.016 28.08 0.084 ;
     RECT  28.104 0.016 28.176 0.084 ;
     RECT  28.2 0.016 28.272 0.084 ;
     RECT  28.296 0.016 28.368 0.084 ;
     RECT  28.392 0.016 28.464 0.084 ;
     RECT  28.488 0.016 28.56 0.084 ;
     RECT  28.584 0.016 28.656 0.084 ;
     RECT  28.68 0.016 28.752 0.084 ;
     RECT  28.776 0.016 28.848 0.084 ;
     RECT  28.872 0.016 28.944 0.084 ;
     RECT  28.968 0.016 29.04 0.084 ;
     RECT  26.064 0.084 29.064 0.131 ;
     RECT  45.288 0.016 45.36 0.084 ;
     RECT  45.384 0.016 45.456 0.084 ;
     RECT  45.48 0.016 45.552 0.084 ;
     RECT  45.576 0.016 45.648 0.084 ;
     RECT  45.672 0.016 45.744 0.084 ;
     RECT  45.768 0.016 45.84 0.084 ;
     RECT  45.864 0.016 45.936 0.084 ;
     RECT  45.96 0.016 46.032 0.084 ;
     RECT  46.056 0.016 46.128 0.084 ;
     RECT  46.152 0.016 46.224 0.084 ;
     RECT  46.248 0.016 46.32 0.084 ;
     RECT  46.344 0.016 46.416 0.084 ;
     RECT  46.44 0.016 46.512 0.084 ;
     RECT  46.536 0.016 46.608 0.084 ;
     RECT  46.632 0.016 46.704 0.084 ;
     RECT  46.728 0.016 46.8 0.084 ;
     RECT  46.824 0.016 46.896 0.084 ;
     RECT  46.92 0.016 46.992 0.084 ;
     RECT  47.016 0.016 47.088 0.084 ;
     RECT  47.112 0.016 47.184 0.084 ;
     RECT  47.208 0.016 47.28 0.084 ;
     RECT  47.304 0.016 47.376 0.084 ;
     RECT  47.4 0.016 47.472 0.084 ;
     RECT  47.496 0.016 47.568 0.084 ;
     RECT  47.592 0.016 47.664 0.084 ;
     RECT  47.688 0.016 47.76 0.084 ;
     RECT  47.784 0.016 47.856 0.084 ;
     RECT  47.88 0.016 47.952 0.084 ;
     RECT  47.976 0.016 48.048 0.084 ;
     RECT  48.072 0.016 48.144 0.084 ;
     RECT  48.168 0.016 48.24 0.084 ;
     RECT  45.264 0.084 48.264 0.131 ;
     RECT  42.624 0.133 42.648 0.275 ;
     RECT  45.456 0.131 48.264 0.323 ;
     RECT  26.16 0.131 29.064 2.137 ;
     RECT  45.456 0.323 48.072 2.137 ;
     RECT  2.4 2.137 2.52 2.151 ;
     RECT  5.1 2.137 5.22 2.151 ;
     RECT  7.8 2.137 7.92 2.151 ;
     RECT  10.5 2.137 10.62 2.151 ;
     RECT  13.2 2.137 13.32 2.151 ;
     RECT  15.9 2.137 16.02 2.151 ;
     RECT  18.6 2.137 18.72 2.151 ;
     RECT  21.3 2.137 21.42 2.151 ;
     RECT  24 2.137 24.12 2.151 ;
     RECT  26.16 2.137 29.52 2.151 ;
     RECT  32.1 2.137 32.22 2.151 ;
     RECT  34.8 2.137 34.92 2.151 ;
     RECT  37.5 2.137 37.62 2.151 ;
     RECT  40.2 2.137 40.32 2.151 ;
     RECT  42.9 2.137 43.02 2.151 ;
     RECT  45.456 2.137 48.42 2.151 ;
     RECT  51 2.137 51.12 2.151 ;
     RECT  53.7 2.137 53.82 2.151 ;
     RECT  56.4 2.137 56.52 2.151 ;
     RECT  59.1 2.137 59.22 2.151 ;
     RECT  61.8 2.137 61.92 2.151 ;
     RECT  21.3 2.151 21.612 2.245 ;
     RECT  24 2.151 24.312 2.245 ;
     RECT  26.16 2.151 29.712 2.245 ;
     RECT  40.2 2.151 40.512 2.245 ;
     RECT  45.456 2.151 48.612 2.245 ;
     RECT  26.16 2.245 29.88 2.291 ;
     RECT  42.9 2.151 43.212 2.293 ;
     RECT  29.4 2.291 29.88 2.533 ;
     RECT  7.8 2.151 8.112 2.677 ;
     RECT  13.2 2.151 13.512 2.677 ;
     RECT  21.3 2.245 21.96 2.821 ;
     RECT  34.8 2.151 35.112 2.821 ;
     RECT  12.576 2.677 13.512 2.867 ;
     RECT  26.16 2.291 28.104 2.915 ;
     RECT  44.64 2.245 48.612 2.915 ;
     RECT  20.448 2.821 21.96 3.157 ;
     RECT  42.9 2.293 43.608 3.203 ;
     RECT  40.2 2.245 41.4 3.299 ;
     RECT  23.808 2.245 24.312 3.301 ;
     RECT  20.448 3.157 22.296 3.637 ;
     RECT  23.808 3.301 24.408 3.637 ;
     RECT  7.8 2.677 9.096 3.875 ;
     RECT  20.448 3.637 24.408 3.875 ;
     RECT  29.4 2.533 30.36 3.923 ;
     RECT  37.5 2.151 37.812 3.925 ;
     RECT  34.8 2.821 35.88 4.163 ;
     RECT  40.2 3.299 40.512 4.261 ;
     RECT  42.9 3.203 43.212 4.405 ;
     RECT  14.544 3.877 14.568 4.451 ;
     RECT  13.2 2.867 13.512 4.501 ;
     RECT  44.64 2.915 47.112 4.691 ;
     RECT  40.2 4.261 41.016 4.741 ;
     RECT  42.768 4.405 43.212 4.789 ;
     RECT  51 2.151 51.312 4.885 ;
     RECT  45.504 4.691 47.112 5.171 ;
     RECT  37.5 3.925 38.232 5.173 ;
     RECT  21.3 3.875 24.408 5.219 ;
     RECT  13.2 4.501 14.424 5.221 ;
     RECT  13.104 5.221 14.424 5.363 ;
     RECT  39.552 4.741 41.016 5.459 ;
     RECT  22.992 5.219 24.408 5.555 ;
     RECT  49.872 5.029 49.896 5.605 ;
     RECT  51 4.885 51.432 5.605 ;
     RECT  40.2 5.459 41.016 5.651 ;
     RECT  26.7 2.915 27.912 5.747 ;
     RECT  42.144 4.789 43.212 5.747 ;
     RECT  45.504 5.171 46.776 5.747 ;
     RECT  24 5.555 24.408 5.795 ;
     RECT  45.504 5.747 46.488 5.845 ;
     RECT  45.024 5.845 46.488 6.131 ;
     RECT  13.2 5.363 14.424 6.229 ;
     RECT  48.3 2.915 48.612 6.277 ;
     RECT  45.024 6.131 46.392 6.563 ;
     RECT  34.8 4.163 35.112 6.805 ;
     RECT  49.872 5.605 51.432 6.805 ;
     RECT  49.872 6.805 52.008 6.851 ;
     RECT  49.872 6.851 49.896 6.947 ;
     RECT  51 6.851 52.008 7.333 ;
     RECT  13.2 6.229 14.856 7.379 ;
     RECT  24 5.795 24.312 7.381 ;
     RECT  26.7 5.747 27.012 7.429 ;
     RECT  42.72 5.747 43.212 7.429 ;
     RECT  45.6 6.563 46.392 7.715 ;
     RECT  26.7 7.429 27.144 7.717 ;
     RECT  29.4 3.923 29.712 7.717 ;
     RECT  26.592 7.717 27.144 7.763 ;
     RECT  29.4 7.717 30.264 7.859 ;
     RECT  48.3 6.277 48.744 7.909 ;
     RECT  24 7.381 24.648 8.003 ;
     RECT  37.5 5.173 38.424 8.003 ;
     RECT  37.5 8.003 37.944 8.245 ;
     RECT  17.232 7.909 17.256 8.485 ;
     RECT  18.6 2.151 18.912 8.485 ;
     RECT  51 7.333 52.488 8.485 ;
     RECT  17.232 8.485 18.912 8.531 ;
     RECT  55.296 7.957 55.32 8.675 ;
     RECT  34.8 6.805 35.304 8.723 ;
     RECT  24 8.003 24.312 8.965 ;
     RECT  17.616 8.531 18.912 9.061 ;
     RECT  42.384 7.429 43.212 9.061 ;
     RECT  48.3 7.909 48.984 9.061 ;
     RECT  26.592 7.763 27.012 9.107 ;
     RECT  50.736 8.485 52.488 9.107 ;
     RECT  32.1 2.151 32.412 9.349 ;
     RECT  21.3 5.219 21.612 9.637 ;
     RECT  42.384 9.061 43.992 9.637 ;
     RECT  48.3 9.061 49.56 9.637 ;
     RECT  48.192 9.637 49.56 9.731 ;
     RECT  17.616 9.061 19.416 9.779 ;
     RECT  48.192 9.731 48.612 10.211 ;
     RECT  40.2 5.651 40.632 10.213 ;
     RECT  51 9.107 52.488 10.213 ;
     RECT  53.7 2.151 54.012 10.213 ;
     RECT  37.344 8.245 37.944 10.307 ;
     RECT  55.296 9.637 55.32 10.307 ;
     RECT  18.6 9.779 19.416 10.355 ;
     RECT  42.192 9.637 43.992 10.595 ;
     RECT  34.8 8.723 35.112 10.693 ;
     RECT  42.336 10.595 43.992 10.739 ;
     RECT  34.8 10.693 35.592 10.789 ;
     RECT  31.632 9.349 32.412 10.931 ;
     RECT  34.8 10.789 35.736 10.931 ;
     RECT  39.744 10.213 40.632 10.931 ;
     RECT  40.2 10.931 40.632 11.125 ;
     RECT  13.2 7.379 14.424 11.171 ;
     RECT  21.168 9.637 21.612 11.653 ;
     RECT  22.992 5.555 23.016 11.653 ;
     RECT  51 10.213 54.012 11.699 ;
     RECT  18.6 10.355 19.32 11.941 ;
     RECT  21.168 11.653 23.016 11.941 ;
     RECT  53.7 11.699 54.012 11.941 ;
     RECT  20.784 11.941 23.016 12.227 ;
     RECT  30.72 11.509 30.744 12.563 ;
     RECT  24 8.965 25.128 12.755 ;
     RECT  42.336 10.739 43.212 12.755 ;
     RECT  17.616 11.941 19.32 13.139 ;
     RECT  51 11.699 52.488 13.139 ;
     RECT  32.1 10.931 32.412 13.525 ;
     RECT  53.7 11.941 54.12 13.811 ;
     RECT  20.784 12.227 21.612 13.859 ;
     RECT  29.4 7.859 29.712 13.909 ;
     RECT  37.344 10.307 37.812 13.955 ;
     RECT  22.992 12.227 23.016 14.005 ;
     RECT  24 12.755 24.696 14.005 ;
     RECT  26.7 9.107 27.012 14.005 ;
     RECT  15.9 2.151 16.212 14.197 ;
     RECT  42.9 12.755 43.212 14.197 ;
     RECT  51 13.139 51.432 14.197 ;
     RECT  52.464 13.139 52.488 14.197 ;
     RECT  34.8 10.931 35.592 14.243 ;
     RECT  40.2 11.125 41.016 14.339 ;
     RECT  29.28 13.909 29.712 14.387 ;
     RECT  51 14.197 52.488 14.387 ;
     RECT  32.1 13.525 33.048 14.483 ;
     RECT  45.6 7.715 45.912 14.677 ;
     RECT  45.6 14.677 46.104 14.819 ;
     RECT  26.7 14.005 27.384 15.107 ;
     RECT  51 14.387 51.624 15.155 ;
     RECT  42.9 14.197 43.992 15.301 ;
     RECT  45.6 14.819 45.912 15.301 ;
     RECT  22.992 14.005 24.696 15.637 ;
     RECT  32.1 14.483 32.412 16.357 ;
     RECT  37.5 13.955 37.812 16.357 ;
     RECT  51 15.155 51.432 16.357 ;
     RECT  15.9 14.197 16.344 16.403 ;
     RECT  18.6 13.139 19.32 16.501 ;
     RECT  53.7 13.811 54.012 16.501 ;
     RECT  36.48 15.829 36.504 16.547 ;
     RECT  37.5 16.357 37.944 16.547 ;
     RECT  22.992 15.637 24.84 16.595 ;
     RECT  51 16.357 51.864 17.075 ;
     RECT  42.9 15.301 45.912 17.123 ;
     RECT  51 17.075 51.768 17.171 ;
     RECT  53.7 16.501 54.936 17.459 ;
     RECT  31.968 16.357 32.412 17.461 ;
     RECT  34.8 14.243 35.496 17.653 ;
     RECT  18.6 16.501 19.944 18.275 ;
     RECT  40.2 14.339 40.512 18.277 ;
     RECT  13.2 11.171 13.512 18.565 ;
     RECT  15.9 16.403 16.212 18.565 ;
     RECT  18.6 18.275 19.32 18.565 ;
     RECT  15.408 18.565 16.212 18.709 ;
     RECT  31.296 17.461 32.412 18.755 ;
     RECT  13.2 18.565 13.608 18.757 ;
     RECT  15.408 18.709 16.344 18.757 ;
     RECT  53.7 17.459 54.012 18.757 ;
     RECT  22.992 16.595 23.016 18.851 ;
     RECT  34.032 17.653 35.496 18.851 ;
     RECT  41.568 18.133 41.592 18.899 ;
     RECT  37.5 16.547 37.812 19.285 ;
     RECT  45.6 17.123 45.912 19.333 ;
     RECT  18 18.565 19.32 19.427 ;
     RECT  53.7 18.757 54.696 19.475 ;
     RECT  26.7 15.107 27.012 19.621 ;
     RECT  42.9 17.123 43.944 19.909 ;
     RECT  18.6 19.427 19.32 20.003 ;
     RECT  45.6 19.333 46.728 20.003 ;
     RECT  42.9 19.909 44.616 20.053 ;
     RECT  34.8 18.851 35.496 20.099 ;
     RECT  42.528 20.053 44.616 20.245 ;
     RECT  36.48 19.813 36.504 20.389 ;
     RECT  37.5 19.285 38.472 20.389 ;
     RECT  18.6 20.003 18.912 20.437 ;
     RECT  15.168 18.757 16.344 20.485 ;
     RECT  39.792 18.277 40.512 20.485 ;
     RECT  51 17.171 51.432 20.485 ;
     RECT  29.4 14.387 29.712 20.581 ;
     RECT  15.168 20.485 16.824 20.725 ;
     RECT  26.064 19.621 27.012 20.917 ;
     RECT  36.48 20.389 38.472 20.965 ;
     RECT  39.744 20.485 40.512 20.965 ;
     RECT  31.968 18.755 32.412 21.011 ;
     RECT  18.48 20.437 18.912 21.061 ;
     RECT  24 16.595 24.84 21.253 ;
     RECT  26.064 20.917 27.192 21.253 ;
     RECT  36.48 20.965 40.512 21.395 ;
     RECT  41.664 20.245 44.616 21.539 ;
     RECT  29.04 20.581 29.712 21.683 ;
     RECT  51 20.485 52.296 21.731 ;
     RECT  18.48 21.061 19.032 21.781 ;
     RECT  20.016 20.149 20.04 21.781 ;
     RECT  21.3 13.859 21.612 21.781 ;
     RECT  37.296 21.395 40.512 21.781 ;
     RECT  41.664 21.539 44.376 21.781 ;
     RECT  24 21.253 27.192 22.067 ;
     RECT  25.584 22.067 27.192 22.165 ;
     RECT  24 22.067 24.552 22.499 ;
     RECT  51 21.731 51.432 22.835 ;
     RECT  22.608 22.069 22.632 23.027 ;
     RECT  37.296 21.781 44.376 23.269 ;
     RECT  51 22.835 51.312 23.269 ;
     RECT  45.6 20.003 45.912 23.845 ;
     RECT  48.3 10.211 48.612 23.845 ;
     RECT  50.544 23.269 51.312 23.845 ;
     RECT  50.016 23.845 51.312 23.893 ;
     RECT  15.168 20.725 17.496 24.421 ;
     RECT  18.48 21.781 21.612 24.421 ;
     RECT  13.2 18.757 13.656 24.469 ;
     RECT  15.168 24.421 21.612 24.469 ;
     RECT  24 22.499 24.312 24.469 ;
     RECT  13.2 24.469 21.612 24.563 ;
     RECT  50.016 23.893 51.432 24.611 ;
     RECT  14.544 24.563 21.612 24.659 ;
     RECT  45.6 23.845 46.008 24.659 ;
     RECT  51 24.611 51.432 24.659 ;
     RECT  47.328 23.845 48.612 24.899 ;
     RECT  24 24.469 24.408 25.525 ;
     RECT  37.296 23.269 44.472 25.715 ;
     RECT  40.2 25.715 44.472 25.763 ;
     RECT  37.296 25.715 38.76 26.101 ;
     RECT  25.584 22.165 27.288 26.197 ;
     RECT  15.9 24.659 21.612 26.243 ;
     RECT  36.768 26.101 38.76 26.243 ;
     RECT  44.448 25.763 44.472 26.243 ;
     RECT  15.9 26.243 20.28 26.339 ;
     RECT  25.536 26.197 27.288 26.339 ;
     RECT  24 25.525 24.456 26.629 ;
     RECT  14.544 24.659 14.568 27.107 ;
     RECT  24 26.629 24.504 27.301 ;
     RECT  25.536 26.339 27.012 27.301 ;
     RECT  2.4 2.151 2.712 27.819 ;
     RECT  5.1 2.151 5.412 27.819 ;
     RECT  7.8 3.875 8.112 27.819 ;
     RECT  10.5 2.151 10.812 27.819 ;
     RECT  13.2 24.563 13.512 27.819 ;
     RECT  15.9 26.339 19.464 27.819 ;
     RECT  21.3 26.243 21.612 27.819 ;
     RECT  24 27.301 27.012 27.819 ;
     RECT  29.4 21.683 29.712 27.819 ;
     RECT  32.1 21.011 32.412 27.819 ;
     RECT  34.8 20.099 35.112 27.819 ;
     RECT  40.2 25.763 43.212 27.819 ;
     RECT  45.6 24.659 45.912 27.819 ;
     RECT  48.3 24.899 48.612 27.819 ;
     RECT  51 24.659 51.312 27.819 ;
     RECT  53.7 19.475 54.012 27.819 ;
     RECT  56.4 2.151 56.712 27.819 ;
     RECT  59.1 2.151 59.412 27.819 ;
     RECT  61.8 2.151 62.112 27.819 ;
     RECT  2.592 27.819 2.712 27.833 ;
     RECT  5.292 27.819 5.412 27.833 ;
     RECT  7.992 27.819 8.112 27.833 ;
     RECT  10.692 27.819 10.812 27.833 ;
     RECT  13.392 27.819 13.512 27.833 ;
     RECT  16.092 27.819 19.464 27.833 ;
     RECT  21.492 27.819 21.612 27.833 ;
     RECT  24.192 27.819 27.012 27.833 ;
     RECT  29.592 27.819 29.712 27.833 ;
     RECT  32.292 27.819 32.412 27.833 ;
     RECT  34.992 27.819 35.112 27.833 ;
     RECT  40.392 27.819 43.212 27.833 ;
     RECT  45.792 27.819 45.912 27.833 ;
     RECT  48.492 27.819 48.612 27.833 ;
     RECT  51.192 27.819 51.312 27.833 ;
     RECT  53.892 27.819 54.012 27.833 ;
     RECT  56.592 27.819 56.712 27.833 ;
     RECT  59.292 27.819 59.412 27.833 ;
     RECT  61.992 27.819 62.112 27.833 ;
     RECT  24.48 27.833 26.184 29.747 ;
     RECT  36.768 26.243 38.28 30.131 ;
     RECT  16.464 27.833 19.464 30.132 ;
     RECT  16.488 30.132 16.56 30.16 ;
     RECT  16.584 30.132 16.656 30.16 ;
     RECT  16.68 30.132 16.752 30.16 ;
     RECT  16.776 30.132 16.848 30.16 ;
     RECT  16.872 30.132 16.944 30.16 ;
     RECT  16.968 30.132 17.04 30.16 ;
     RECT  17.064 30.132 17.136 30.16 ;
     RECT  17.16 30.132 17.232 30.16 ;
     RECT  17.256 30.132 17.328 30.16 ;
     RECT  17.352 30.132 17.424 30.16 ;
     RECT  17.448 30.132 17.52 30.16 ;
     RECT  17.544 30.132 17.616 30.16 ;
     RECT  17.64 30.132 17.712 30.16 ;
     RECT  17.736 30.132 17.808 30.16 ;
     RECT  17.832 30.132 17.904 30.16 ;
     RECT  17.928 30.132 18 30.16 ;
     RECT  18.024 30.132 18.096 30.16 ;
     RECT  18.12 30.132 18.192 30.16 ;
     RECT  18.216 30.132 18.288 30.16 ;
     RECT  18.312 30.132 18.384 30.16 ;
     RECT  18.408 30.132 18.48 30.16 ;
     RECT  18.504 30.132 18.576 30.16 ;
     RECT  18.6 30.132 18.672 30.16 ;
     RECT  18.696 30.132 18.768 30.16 ;
     RECT  18.792 30.132 18.864 30.16 ;
     RECT  18.888 30.132 18.96 30.16 ;
     RECT  18.984 30.132 19.056 30.16 ;
     RECT  19.08 30.132 19.152 30.16 ;
     RECT  19.176 30.132 19.248 30.16 ;
     RECT  19.272 30.132 19.344 30.16 ;
     RECT  19.368 30.132 19.44 30.16 ;
     RECT  24.48 29.747 24.504 30.179 ;
     RECT  25.536 29.747 26.184 30.179 ;
     RECT  36.768 30.131 38.184 30.179 ;
     RECT  40.656 27.833 42.36 30.179 ;
     RECT  41.4 2.245 42.9 3.299 ;
     RECT  43.212 2.245 44.64 2.293 ;
     RECT  28.104 2.291 29.4 2.915 ;
     RECT  43.608 2.293 44.64 3.203 ;
     RECT  9.096 2.677 10.5 3.875 ;
     RECT  27.912 2.915 29.4 5.747 ;
     RECT  47.112 2.915 48.3 5.171 ;
     RECT  22.296 3.157 23.808 3.637 ;
     RECT  43.212 3.203 44.64 4.691 ;
     RECT  40.512 3.299 42.9 4.261 ;
     RECT  13.512 3.877 14.544 4.451 ;
     RECT  14.568 3.877 15.9 4.451 ;
     RECT  41.016 4.261 42.9 4.405 ;
     RECT  41.016 4.405 42.768 4.789 ;
     RECT  13.512 4.451 15.9 4.501 ;
     RECT  14.424 4.501 15.9 6.229 ;
     RECT  45.024 4.691 45.504 5.845 ;
     RECT  38.232 4.741 39.552 5.173 ;
     RECT  41.016 4.789 42.144 5.651 ;
     RECT  48.612 5.029 49.872 6.277 ;
     RECT  49.896 5.029 51 5.605 ;
     RECT  46.776 5.171 48.3 5.747 ;
     RECT  38.424 5.173 39.552 5.459 ;
     RECT  21.612 5.219 22.992 11.653 ;
     RECT  23.016 5.555 24 14.005 ;
     RECT  40.632 5.651 42.144 5.747 ;
     RECT  14.856 6.229 15.9 7.379 ;
     RECT  48.744 6.277 49.872 6.947 ;
     RECT  49.896 6.851 51 6.947 ;
     RECT  48.744 6.947 48.984 7.909 ;
     RECT  52.488 7.333 53.7 10.213 ;
     RECT  14.424 7.379 15.9 11.171 ;
     RECT  16.212 7.909 17.232 8.531 ;
     RECT  17.256 7.909 18.6 8.485 ;
     RECT  54.012 7.957 55.296 8.675 ;
     RECT  55.32 7.957 56.4 8.675 ;
     RECT  24.312 8.003 24.648 8.965 ;
     RECT  16.212 8.531 17.616 9.779 ;
     RECT  54.012 8.675 56.4 9.637 ;
     RECT  25.128 8.965 26.592 9.107 ;
     RECT  49.56 9.061 50.736 9.107 ;
     RECT  49.56 9.107 51 9.731 ;
     RECT  54.012 9.637 55.296 10.307 ;
     RECT  55.32 9.637 56.4 10.307 ;
     RECT  42.192 10.595 42.336 11.125 ;
     RECT  31.632 10.931 32.1 11.509 ;
     RECT  41.016 11.125 42.336 12.755 ;
     RECT  29.712 11.509 30.72 12.563 ;
     RECT  30.744 11.509 32.1 12.563 ;
     RECT  52.488 11.699 53.7 14.387 ;
     RECT  16.212 11.941 17.616 13.139 ;
     RECT  19.32 11.941 20.784 13.859 ;
     RECT  21.612 12.227 22.992 18.851 ;
     RECT  16.212 13.139 16.344 14.197 ;
     RECT  51.432 13.139 52.464 14.197 ;
     RECT  51.432 15.155 51.624 16.357 ;
     RECT  35.496 15.829 36.48 16.547 ;
     RECT  36.504 15.829 37.5 16.547 ;
     RECT  19.944 16.501 21.3 18.275 ;
     RECT  54.936 16.501 56.4 17.459 ;
     RECT  23.016 16.595 24 18.851 ;
     RECT  54.012 17.459 54.696 18.757 ;
     RECT  40.512 18.133 41.568 18.899 ;
     RECT  41.592 18.133 42.9 18.899 ;
     RECT  13.656 18.757 15.168 24.469 ;
     RECT  40.512 18.899 42.9 20.053 ;
     RECT  38.472 19.285 39.792 20.485 ;
     RECT  18 19.427 18.6 20.437 ;
     RECT  24.84 19.621 26.064 21.253 ;
     RECT  35.496 19.813 36.48 20.099 ;
     RECT  36.504 19.813 37.5 20.389 ;
     RECT  44.616 19.909 45.6 21.539 ;
     RECT  18.912 20.003 19.32 20.149 ;
     RECT  40.512 20.053 42.528 20.245 ;
     RECT  35.112 20.099 36.48 21.395 ;
     RECT  18.912 20.149 20.016 21.061 ;
     RECT  20.04 20.149 21.3 21.781 ;
     RECT  40.512 20.245 41.664 21.781 ;
     RECT  18 20.437 18.48 20.485 ;
     RECT  16.824 20.485 18.48 20.725 ;
     RECT  38.472 20.485 39.744 20.965 ;
     RECT  52.296 20.485 53.7 21.731 ;
     RECT  17.496 20.725 18.48 24.421 ;
     RECT  19.032 21.061 20.016 21.781 ;
     RECT  44.376 21.539 45.6 23.269 ;
     RECT  24.552 22.067 25.584 22.499 ;
     RECT  21.612 22.069 22.608 23.027 ;
     RECT  22.632 22.069 24 23.027 ;
     RECT  24.312 22.499 25.584 24.469 ;
     RECT  51.312 22.835 51.432 23.893 ;
     RECT  44.472 23.269 45.6 26.243 ;
     RECT  46.008 23.845 47.328 24.659 ;
     RECT  48.612 23.845 50.016 24.611 ;
     RECT  24.408 24.469 25.584 25.525 ;
     RECT  13.512 24.563 14.544 27.107 ;
     RECT  14.568 24.659 15.9 27.107 ;
     RECT  45.912 24.659 47.328 24.899 ;
     RECT  24.456 25.525 25.584 26.197 ;
     RECT  38.76 25.715 40.2 26.243 ;
     RECT  43.212 25.763 44.448 26.243 ;
     RECT  24.456 26.197 25.536 26.629 ;
     RECT  20.28 26.243 21.3 26.339 ;
     RECT  24.504 26.629 25.536 27.301 ;
     RECT  24.504 29.747 25.536 30.179 ;
  END
END qfd_landh_128_NS_65x30
END LIBRARY
